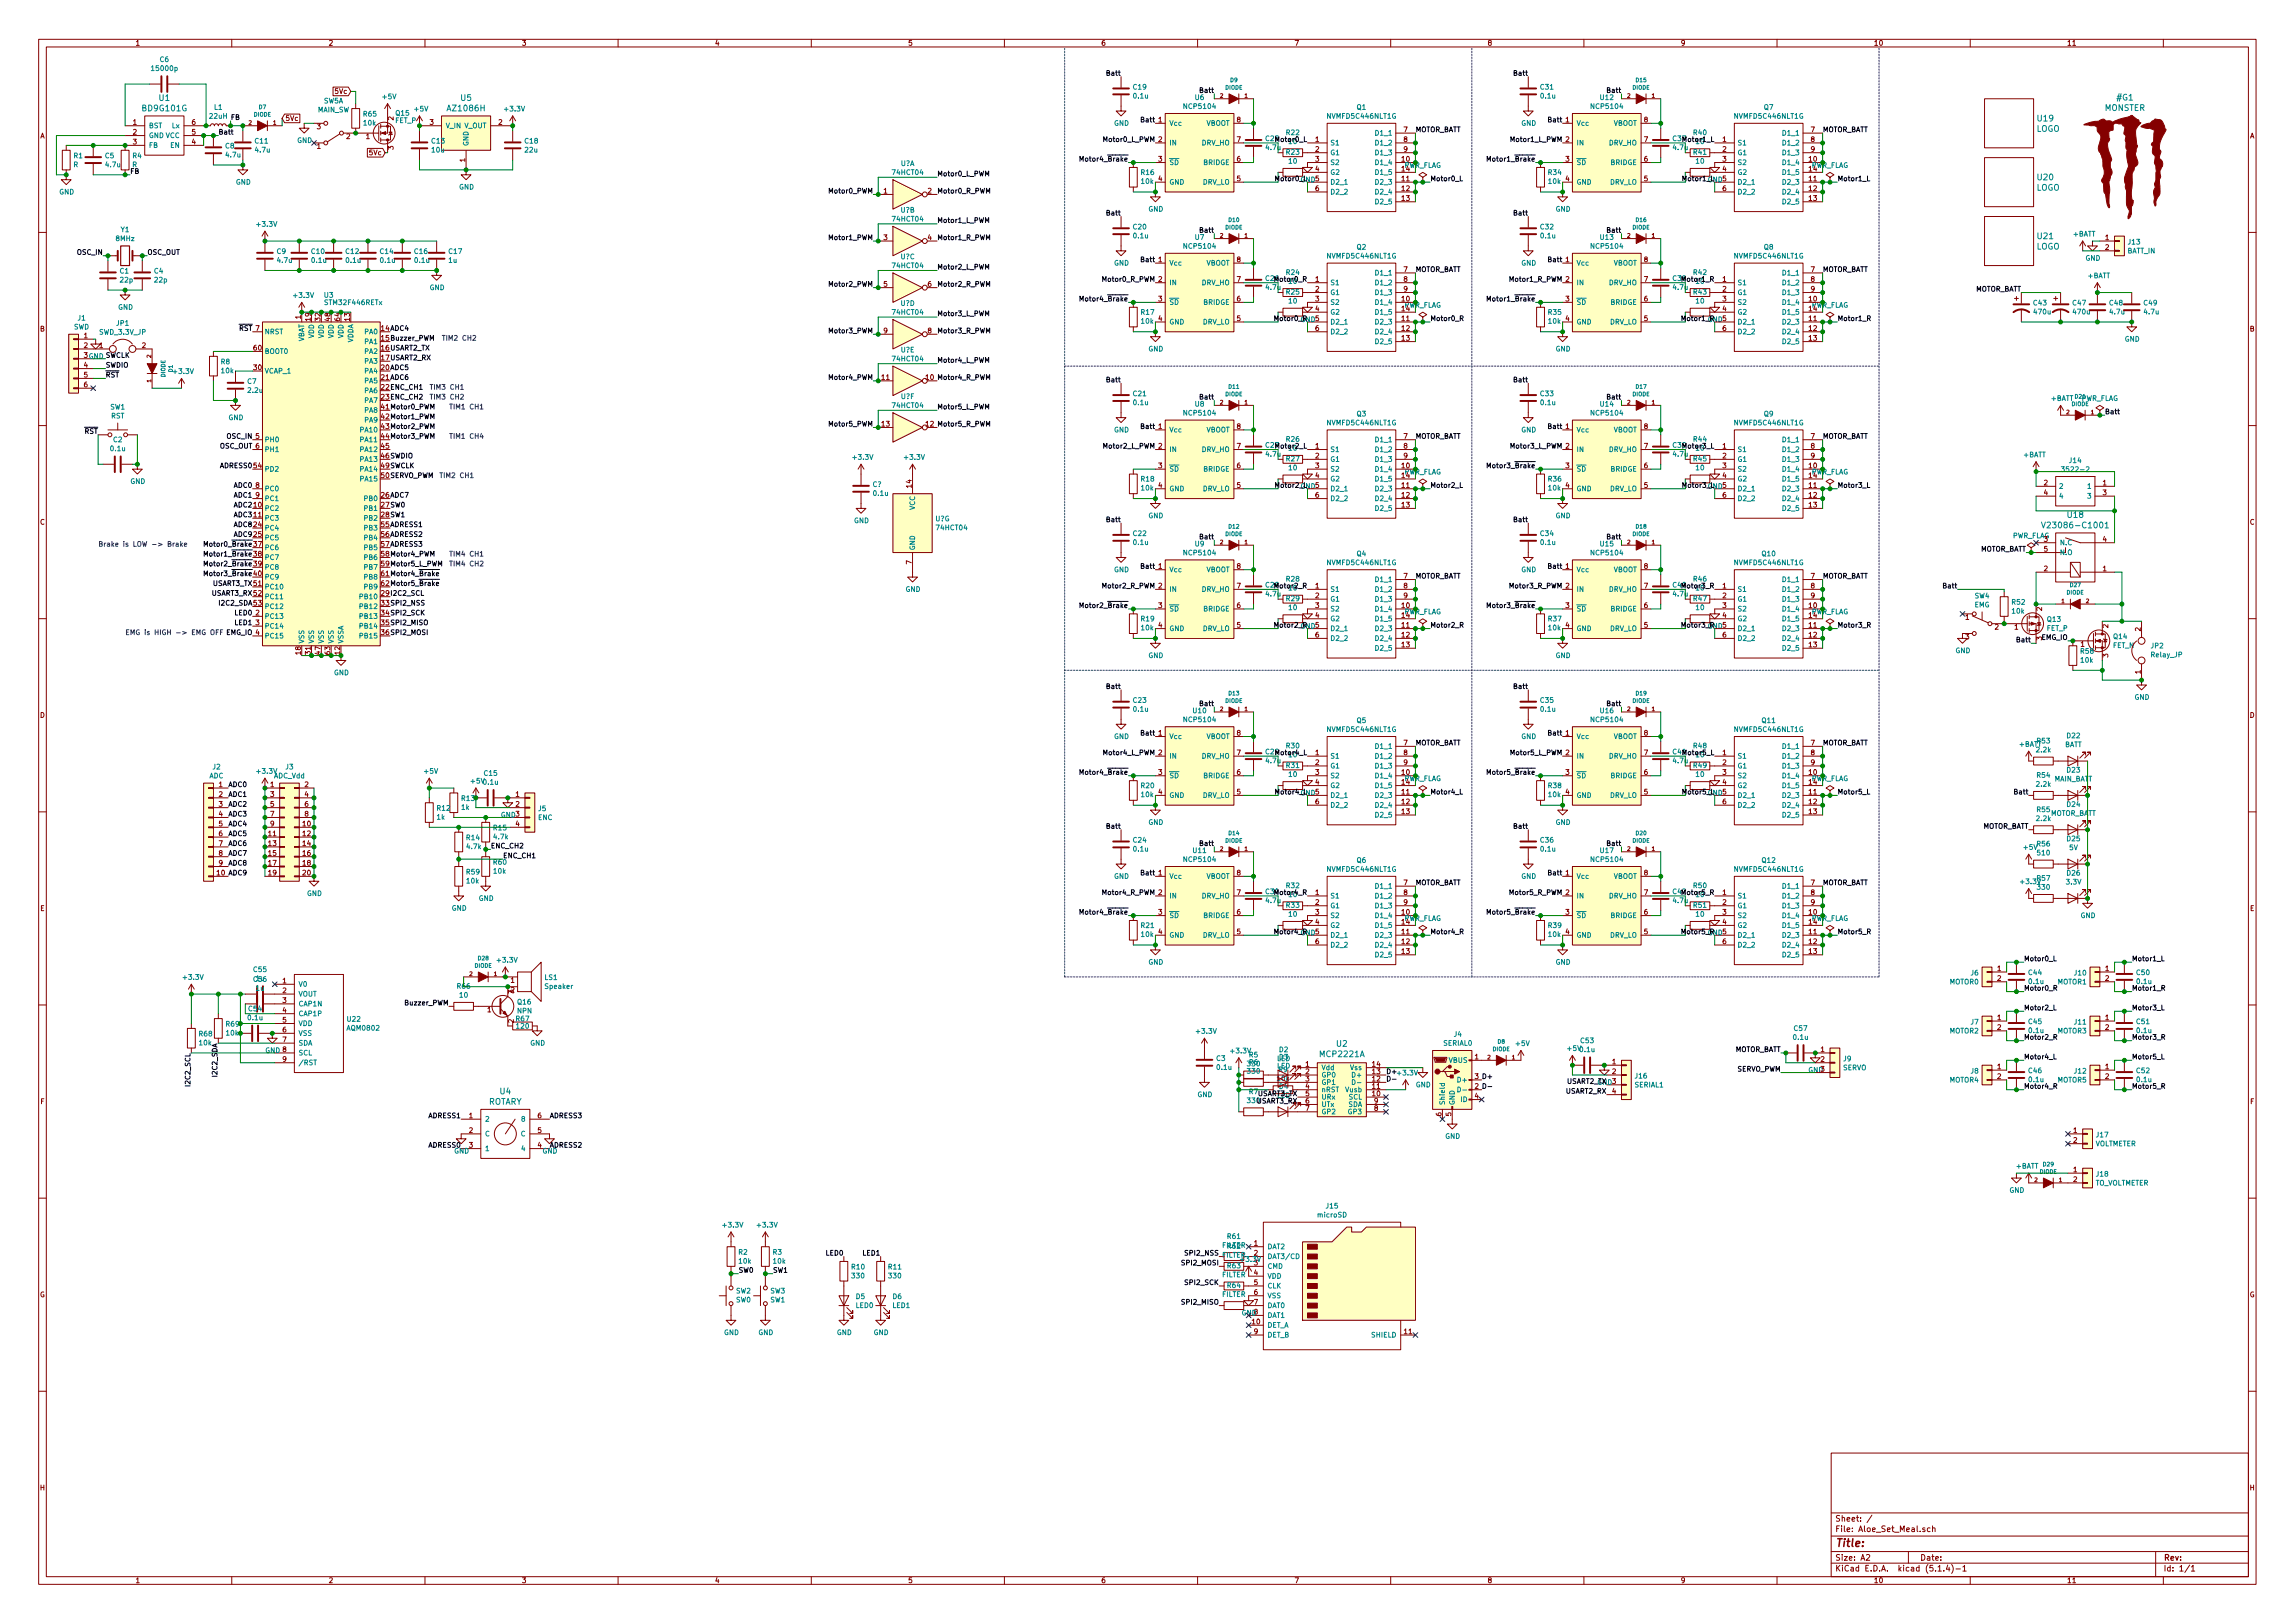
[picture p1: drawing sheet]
<svg xmlns="http://www.w3.org/2000/svg" width="594mm" height="420mm" viewBox="0 0 594 420" stroke-linecap="round" stroke-linejoin="round" font-family="sans-serif">
<defs><g id="words">
<text font-size="2.8" fill="#840000" x="475" y="400.4">Title:</text>
<g font-size="2.1" fill="#008484">
<text x="37" y="28.8">BD9G101G</text>
<text x="41.2" y="26.1">U1</text>
<text x="116.1" y="28.8">AZ1086H</text>
<text x="119.3" y="26.1">U5</text>
<text x="544.8" y="28.7">MONSTER</text>
<text x="548.1" y="26">#G1</text>
<text x="527" y="34.1">LOGO</text>
<text x="527.5" y="31.4">U19</text>
<text x="527.5" y="46.7">U20</text>
<text x="527" y="49.3">LOGO</text>
<text x="527" y="64.6">LOGO</text>
<text x="527.5" y="61.9">U21</text>
<text x="530.1" y="136.7">V23086-C1001</text>
<text x="535.3" y="134.1">U18</text>
<text x="341.9" y="273.7">MCP2221A</text>
<text x="346" y="271">U2</text>
<text x="126.3" y="286">ROTARY</text>
<text x="129.5" y="283.3">U4</text>
</g>
<g font-size="2.1" fill="#840000">
<text x="475" y="393.9">Sheet: /</text>
<text x="475" y="396.6">File: Aloe_Set_Meal.sch</text>
<text x="475" y="406.8">KiCad E.D.A. kicad (5.1.4)-1</text>
<text x="475" y="404">Size: A2</text>
<text x="497" y="404">Date:</text>
<text x="560" y="404">Rev:</text>
<text x="560" y="406.8">Id: 1/1</text>
</g>
<g font-size="1.8" fill="#840000">
<text x="35" y="11.8">1</text>
<text x="85" y="11.8">2</text>
<text x="135" y="11.8">3</text>
<text x="185" y="11.8">4</text>
<text x="235" y="11.8">5</text>
<text x="285" y="11.8">6</text>
<text x="335" y="11.8">7</text>
<text x="385" y="11.8">8</text>
<text x="435" y="11.8">9</text>
<text x="485" y="11.8">10</text>
<text x="535" y="11.8">11</text>
<text x="86.9" y="24.3">5Vc</text>
<text x="10.4" y="35.8">A</text>
<text x="34.4" y="32.3">1</text>
<text x="34.4" y="34.8">2</text>
<text x="49.7" y="34.8">5</text>
<text x="49.7" y="32.3">6</text>
<text x="73.8" y="31.3">5Vc</text>
<text x="82.1" y="33.4">3</text>
<text x="89.7" y="36">2</text>
<text x="94.8" y="36">1</text>
<text x="101.9" y="31.1" transform="rotate(-90 101.9 31.1)">2</text>
<text x="111.3" y="32.3">3</text>
<text x="129.1" y="32.3">2</text>
<text x="320.2" y="31.7">8</text>
<text x="363.4" y="34.2">7</text>
<text x="425.6" y="31.7">8</text>
<text x="468.8" y="34.2">7</text>
<text x="582.4" y="35.8">A</text>
<text x="34.4" y="37.4">3</text>
<text x="49.7" y="37.4">4</text>
<text x="82.1" y="38.5">1</text>
<text x="95.8" y="40.2">5Vc</text>
<text x="101.9" y="38.8" transform="rotate(-90 101.9 38.8)">3</text>
<text x="120.4" y="41.9" transform="rotate(-90 120.4 41.9)">1</text>
<text x="299.9" y="36.7">2</text>
<text x="299.9" y="41.8">3</text>
<text x="320.2" y="41.8">6</text>
<text x="320.2" y="36.7">7</text>
<text x="340.5" y="36.7">1</text>
<text x="340.5" y="39.3">2</text>
<text x="340.5" y="41.8">3</text>
<text x="362.9" y="41.8">10</text>
<text x="363.4" y="36.7">8</text>
<text x="363.4" y="39.3">9</text>
<text x="405.3" y="36.7">2</text>
<text x="405.3" y="41.8">3</text>
<text x="425.6" y="41.8">6</text>
<text x="425.6" y="36.7">7</text>
<text x="445.9" y="36.7">1</text>
<text x="445.9" y="39.3">2</text>
<text x="445.9" y="41.8">3</text>
<text x="468.3" y="41.8">10</text>
<text x="468.8" y="36.7">8</text>
<text x="468.8" y="39.3">9</text>
<text x="299.9" y="46.9">4</text>
<text x="320.2" y="46.9">5</text>
<text x="340.5" y="44.4">4</text>
<text x="362.9" y="46.9">11</text>
<text x="362.9" y="44.4">14</text>
<text x="405.3" y="46.9">4</text>
<text x="425.6" y="46.9">5</text>
<text x="445.9" y="44.4">4</text>
<text x="468.3" y="46.9">11</text>
<text x="468.3" y="44.4">14</text>
<text x="228.8" y="50.1">1</text>
<text x="240.2" y="50.1">2</text>
<text x="340.5" y="49.4">6</text>
<text x="362.9" y="49.4">12</text>
<text x="362.9" y="52">13</text>
<text x="445.9" y="49.4">6</text>
<text x="468.3" y="49.4">12</text>
<text x="468.3" y="52">13</text>
<text x="228.8" y="62.1">3</text>
<text x="240.2" y="62.1">4</text>
<text x="545" y="62.1">1</text>
<text x="545" y="64.7">2</text>
<text x="320.2" y="67.9">8</text>
<text x="363.4" y="70.4">7</text>
<text x="425.6" y="67.9">8</text>
<text x="468.8" y="70.4">7</text>
<text x="228.8" y="74.2">5</text>
<text x="240.2" y="74.2">6</text>
<text x="320.2" y="72.9">7</text>
<text x="340.5" y="72.9">1</text>
<text x="340.5" y="75.5">2</text>
<text x="363.4" y="72.9">8</text>
<text x="363.4" y="75.5">9</text>
<text x="425.6" y="72.9">7</text>
<text x="445.9" y="72.9">1</text>
<text x="445.9" y="75.5">2</text>
<text x="468.8" y="72.9">8</text>
<text x="468.8" y="75.5">9</text>
<text x="77.9" y="82.6" transform="rotate(-90 77.9 82.6)">1</text>
<text x="80.4" y="83" transform="rotate(-90 80.4 83)">19</text>
<text x="82.9" y="83" transform="rotate(-90 82.9 83)">32</text>
<text x="85.5" y="83" transform="rotate(-90 85.5 83)">48</text>
<text x="88" y="83" transform="rotate(-90 88 83)">64</text>
<text x="90.6" y="83" transform="rotate(-90 90.6 83)">13</text>
<text x="299.9" y="78">3</text>
<text x="299.9" y="83.1">4</text>
<text x="320.2" y="83.1">5</text>
<text x="320.2" y="78">6</text>
<text x="340.5" y="78">3</text>
<text x="340.5" y="80.6">4</text>
<text x="362.9" y="78">10</text>
<text x="362.9" y="83.1">11</text>
<text x="362.9" y="80.6">14</text>
<text x="405.3" y="78">3</text>
<text x="405.3" y="83.1">4</text>
<text x="425.6" y="83.1">5</text>
<text x="425.6" y="78">6</text>
<text x="445.9" y="78">3</text>
<text x="445.9" y="80.6">4</text>
<text x="468.3" y="78">10</text>
<text x="468.3" y="83.1">11</text>
<text x="468.3" y="80.6">14</text>
<text x="10.4" y="85.8">B</text>
<text x="21.7" y="87.5">1</text>
<text x="228.8" y="86.3">9</text>
<text x="240.2" y="86.3">8</text>
<text x="340.5" y="85.6">6</text>
<text x="362.9" y="85.6">12</text>
<text x="362.9" y="88.2">13</text>
<text x="445.9" y="85.6">6</text>
<text x="468.3" y="85.6">12</text>
<text x="468.3" y="88.2">13</text>
<text x="582.4" y="85.8">B</text>
<text x="21.7" y="90.1">2</text>
<text x="21.7" y="95.2">4</text>
<text x="25.7" y="90.1">1</text>
<text x="36.8" y="90.1">2</text>
<text x="65.7" y="90.7">60</text>
<text x="65.7" y="95.8">30</text>
<text x="21.7" y="97.7">5</text>
<text x="21.7" y="100.2">6</text>
<text x="228.3" y="98.3">11</text>
<text x="228.3" y="110.4">13</text>
<text x="320.2" y="111">8</text>
<text x="363.4" y="113.6">7</text>
<text x="425.6" y="111">8</text>
<text x="468.8" y="113.6">7</text>
<text x="98.7" y="116.1">45</text>
<text x="299.9" y="116.1">2</text>
<text x="320.2" y="116.1">7</text>
<text x="340.5" y="116.1">1</text>
<text x="340.5" y="118.7">2</text>
<text x="363.4" y="116.1">8</text>
<text x="363.4" y="118.7">9</text>
<text x="405.3" y="116.1">2</text>
<text x="425.6" y="116.1">7</text>
<text x="445.9" y="116.1">1</text>
<text x="445.9" y="118.7">2</text>
<text x="468.8" y="116.1">8</text>
<text x="468.8" y="118.7">9</text>
<text x="65.7" y="121.2">54</text>
<text x="299.9" y="121.2">3</text>
<text x="320.2" y="121.2">6</text>
<text x="340.5" y="121.2">3</text>
<text x="340.5" y="123.7">4</text>
<text x="362.9" y="121.2">10</text>
<text x="362.9" y="123.7">14</text>
<text x="405.3" y="121.2">3</text>
<text x="425.6" y="121.2">6</text>
<text x="445.9" y="121.2">3</text>
<text x="445.9" y="123.7">4</text>
<text x="468.3" y="121.2">10</text>
<text x="468.3" y="123.7">14</text>
<text x="529.1" y="125.6">2</text>
<text x="544.3" y="125.6">1</text>
<text x="65.7" y="131.4">10</text>
<text x="66.2" y="126.3">8</text>
<text x="66.2" y="128.8">9</text>
<text x="236" y="126.2" transform="rotate(-90 236 126.2)">14</text>
<text x="299.9" y="126.3">4</text>
<text x="320.2" y="126.3">5</text>
<text x="340.5" y="128.8">6</text>
<text x="362.9" y="126.3">11</text>
<text x="362.9" y="128.8">12</text>
<text x="362.9" y="131.4">13</text>
<text x="405.3" y="126.3">4</text>
<text x="425.6" y="126.3">5</text>
<text x="445.9" y="128.8">6</text>
<text x="468.3" y="126.3">11</text>
<text x="468.3" y="128.8">12</text>
<text x="468.3" y="131.4">13</text>
<text x="529.1" y="128.2">4</text>
<text x="544.3" y="128.2">3</text>
<text x="10.4" y="135.8">C</text>
<text x="65.7" y="133.9">11</text>
<text x="65.7" y="136.4">24</text>
<text x="582.4" y="135.8">C</text>
<text x="65.7" y="139">25</text>
<text x="529.1" y="140.3">3</text>
<text x="529.1" y="142.8">5</text>
<text x="544.3" y="140.3">4</text>
<text x="236" y="146.1" transform="rotate(-90 236 146.1)">7</text>
<text x="320.2" y="147.2">8</text>
<text x="363.4" y="149.8">7</text>
<text x="425.6" y="147.2">8</text>
<text x="468.8" y="149.8">7</text>
<text x="529.1" y="147.9">2</text>
<text x="544.3" y="147.9">1</text>
<text x="320.2" y="152.3">7</text>
<text x="340.5" y="152.3">1</text>
<text x="340.5" y="154.9">2</text>
<text x="363.4" y="152.3">8</text>
<text x="363.4" y="154.9">9</text>
<text x="425.6" y="152.3">7</text>
<text x="445.9" y="152.3">1</text>
<text x="445.9" y="154.9">2</text>
<text x="468.8" y="152.3">8</text>
<text x="468.8" y="154.9">9</text>
<text x="66.2" y="159.3">2</text>
<text x="66.2" y="161.8">3</text>
<text x="299.9" y="157.4">3</text>
<text x="320.2" y="157.4">6</text>
<text x="340.5" y="157.4">3</text>
<text x="340.5" y="159.9">4</text>
<text x="362.9" y="157.4">10</text>
<text x="362.9" y="159.9">14</text>
<text x="405.3" y="157.4">3</text>
<text x="425.6" y="157.4">6</text>
<text x="445.9" y="157.4">3</text>
<text x="445.9" y="159.9">4</text>
<text x="468.3" y="157.4">10</text>
<text x="468.3" y="159.9">14</text>
<text x="508.8" y="160.4">1</text>
<text x="528.6" y="158.1" transform="rotate(-90 528.6 158.1)">2</text>
<text x="299.9" y="162.5">4</text>
<text x="320.2" y="162.5">5</text>
<text x="340.5" y="165">6</text>
<text x="362.9" y="162.5">11</text>
<text x="362.9" y="165">12</text>
<text x="362.9" y="167.6">13</text>
<text x="405.3" y="162.5">4</text>
<text x="425.6" y="162.5">5</text>
<text x="445.9" y="165">6</text>
<text x="468.3" y="162.5">11</text>
<text x="468.3" y="165">12</text>
<text x="468.3" y="167.6">13</text>
<text x="508.8" y="165.5">3</text>
<text x="516.4" y="163">2</text>
<text x="521.5" y="163">1</text>
<text x="538.6" y="167.4">1</text>
<text x="545.7" y="162.6" transform="rotate(-90 545.7 162.6)">2</text>
<text x="554.1" y="163.4" transform="rotate(-90 554.1 163.4)">2</text>
<text x="77.9" y="169.4" transform="rotate(-90 77.9 169.4)">18</text>
<text x="80.4" y="169.4" transform="rotate(-90 80.4 169.4)">31</text>
<text x="82.9" y="169.4" transform="rotate(-90 82.9 169.4)">47</text>
<text x="85.5" y="169.4" transform="rotate(-90 85.5 169.4)">63</text>
<text x="88" y="169.4" transform="rotate(-90 88 169.4)">12</text>
<text x="545.7" y="170.2" transform="rotate(-90 545.7 170.2)">3</text>
<text x="554.1" y="174.4" transform="rotate(-90 554.1 174.4)">1</text>
<text x="10.4" y="185.8">D</text>
<text x="582.4" y="185.8">D</text>
<text x="320.2" y="190.4">8</text>
<text x="425.6" y="190.4">8</text>
<text x="299.9" y="195.5">2</text>
<text x="320.2" y="195.5">7</text>
<text x="340.5" y="195.5">1</text>
<text x="363.4" y="193">7</text>
<text x="363.4" y="195.5">8</text>
<text x="405.3" y="195.5">2</text>
<text x="425.6" y="195.5">7</text>
<text x="445.9" y="195.5">1</text>
<text x="468.8" y="193">7</text>
<text x="468.8" y="195.5">8</text>
<text x="56.7" y="203.8">1</text>
<text x="70" y="203.8">1</text>
<text x="78.9" y="203.8">2</text>
<text x="299.9" y="200.6">3</text>
<text x="320.2" y="200.6">6</text>
<text x="340.5" y="198">2</text>
<text x="340.5" y="200.6">3</text>
<text x="340.5" y="203.1">4</text>
<text x="362.9" y="200.6">10</text>
<text x="362.9" y="203.1">14</text>
<text x="363.4" y="198">9</text>
<text x="405.3" y="200.6">3</text>
<text x="425.6" y="200.6">6</text>
<text x="445.9" y="198">2</text>
<text x="445.9" y="200.6">3</text>
<text x="445.9" y="203.1">4</text>
<text x="468.3" y="200.6">10</text>
<text x="468.3" y="203.1">14</text>
<text x="468.8" y="198">9</text>
<text x="56.7" y="206.3">2</text>
<text x="56.7" y="208.8">3</text>
<text x="70" y="206.3">3</text>
<text x="70" y="208.8">5</text>
<text x="78.9" y="206.3">4</text>
<text x="78.9" y="208.8">6</text>
<text x="133.5" y="206.3">1</text>
<text x="133.5" y="208.8">2</text>
<text x="299.9" y="205.7">4</text>
<text x="320.2" y="205.7">5</text>
<text x="340.5" y="208.2">6</text>
<text x="362.9" y="205.7">11</text>
<text x="362.9" y="208.2">12</text>
<text x="405.3" y="205.7">4</text>
<text x="425.6" y="205.7">5</text>
<text x="445.9" y="208.2">6</text>
<text x="468.3" y="205.7">11</text>
<text x="468.3" y="208.2">12</text>
<text x="56.7" y="211.4">4</text>
<text x="56.7" y="213.9">5</text>
<text x="70" y="211.4">7</text>
<text x="70" y="213.9">9</text>
<text x="78.4" y="213.9">10</text>
<text x="78.9" y="211.4">8</text>
<text x="133.5" y="213.9">4</text>
<text x="362.9" y="210.7">13</text>
<text x="468.3" y="210.7">13</text>
<text x="56.7" y="216.5">6</text>
<text x="56.7" y="219">7</text>
<text x="56.7" y="221.5">8</text>
<text x="69.5" y="216.5">11</text>
<text x="69.5" y="219">13</text>
<text x="69.5" y="221.5">15</text>
<text x="78.4" y="216.5">12</text>
<text x="78.4" y="219">14</text>
<text x="78.4" y="221.5">16</text>
<text x="56.7" y="224.1">9</text>
<text x="69.5" y="224.1">17</text>
<text x="69.5" y="226.6">19</text>
<text x="78.4" y="224.1">18</text>
<text x="78.4" y="226.6">20</text>
<text x="320.2" y="226.6">8</text>
<text x="425.6" y="226.6">8</text>
<text x="320.2" y="231.7">7</text>
<text x="340.5" y="231.7">1</text>
<text x="363.4" y="229.2">7</text>
<text x="363.4" y="231.7">8</text>
<text x="425.6" y="231.7">7</text>
<text x="445.9" y="231.7">1</text>
<text x="468.8" y="229.2">7</text>
<text x="468.8" y="231.7">8</text>
<text x="10.4" y="235.8">E</text>
<text x="299.9" y="236.8">3</text>
<text x="320.2" y="236.8">6</text>
<text x="340.5" y="234.2">2</text>
<text x="340.5" y="236.8">3</text>
<text x="340.5" y="239.3">4</text>
<text x="362.9" y="236.8">10</text>
<text x="362.9" y="239.3">14</text>
<text x="363.4" y="234.2">9</text>
<text x="405.3" y="236.8">3</text>
<text x="425.6" y="236.8">6</text>
<text x="445.9" y="234.2">2</text>
<text x="445.9" y="236.8">3</text>
<text x="445.9" y="239.3">4</text>
<text x="468.3" y="236.8">10</text>
<text x="468.3" y="239.3">14</text>
<text x="468.8" y="234.2">9</text>
<text x="582.4" y="235.8">E</text>
<text x="299.9" y="241.9">4</text>
<text x="320.2" y="241.9">5</text>
<text x="340.5" y="244.4">6</text>
<text x="362.9" y="241.9">11</text>
<text x="362.9" y="244.4">12</text>
<text x="405.3" y="241.9">4</text>
<text x="425.6" y="241.9">5</text>
<text x="445.9" y="244.4">6</text>
<text x="468.3" y="241.9">11</text>
<text x="468.3" y="244.4">12</text>
<text x="362.9" y="246.9">13</text>
<text x="468.3" y="246.9">13</text>
<text x="517" y="251.4">1</text>
<text x="545" y="251.4">1</text>
<text x="73.2" y="254.6">1</text>
<text x="73.2" y="257.1">2</text>
<text x="132.2" y="254.4">1</text>
<text x="132.2" y="257">2</text>
<text x="133" y="257.2" transform="rotate(-90 133 257.2)">3</text>
<text x="517" y="253.9">2</text>
<text x="545" y="253.9">2</text>
<text x="73.2" y="259.6">3</text>
<text x="73.2" y="262.2">4</text>
<text x="126.2" y="262">1</text>
<text x="73.2" y="264.7">5</text>
<text x="73.2" y="267.3">6</text>
<text x="73.2" y="269.8">7</text>
<text x="133" y="264.8" transform="rotate(-90 133 264.8)">2</text>
<text x="517" y="264.1">1</text>
<text x="517" y="266.6">2</text>
<text x="545" y="264.1">1</text>
<text x="545" y="266.6">2</text>
<text x="73.2" y="274.9">9</text>
<text x="381.8" y="274.2">1</text>
<text x="417.3" y="275.5">1</text>
<text x="471.3" y="272.3">1</text>
<text x="471.3" y="274.9">2</text>
<text x="330.6" y="279.8">10k</text>
<text x="331.2" y="281.9">D4</text>
<text x="338" y="276.1">1</text>
<text x="338" y="278">2</text>
<text x="338" y="280">3</text>
<text x="338" y="281.9">4</text>
<text x="355.3" y="281.9">11</text>
<text x="355.3" y="280">12</text>
<text x="355.3" y="278">13</text>
<text x="355.3" y="276.1">14</text>
<text x="417.3" y="278">2</text>
<text x="468.1" y="277.7">GND3</text>
<text x="517" y="276.8">1</text>
<text x="517" y="279.3">2</text>
<text x="545" y="276.8">1</text>
<text x="545" y="279.3">2</text>
<text x="10.5" y="285.8">F</text>
<text x="338" y="283.8">5</text>
<text x="338" y="285.7">6</text>
<text x="338" y="287.6">7</text>
<text x="355.3" y="283.8">10</text>
<text x="355.8" y="287.6">8</text>
<text x="355.8" y="285.7">9</text>
<text x="381.8" y="284.4">4</text>
<text x="417.3" y="283.1">4</text>
<text x="582.5" y="285.8">F</text>
<text x="121.4" y="289.5">1</text>
<text x="121.4" y="293.3">2</text>
<text x="139.2" y="293.3">5</text>
<text x="139.2" y="289.5">6</text>
<text x="373.1" y="288.9" transform="rotate(-90 373.1 288.9)">6</text>
<text x="375.7" y="288.9" transform="rotate(-90 375.7 288.9)">5</text>
<text x="536.7" y="293.3">1</text>
<text x="121.4" y="297.1">3</text>
<text x="139.2" y="297.1">4</text>
<text x="536.7" y="295.8">2</text>
<text x="536.7" y="303.4">1</text>
<text x="536.7" y="306">2</text>
<text x="324.6" y="322.5">1</text>
<text x="324.6" y="325">2</text>
<text x="324.6" y="327.6">3</text>
<text x="10.3" y="335.8">G</text>
<text x="324.6" y="330.1">4</text>
<text x="324.6" y="332.7">5</text>
<text x="324.6" y="335.2">6</text>
<text x="582.3" y="335.8">G</text>
<text x="324.6" y="337.7">7</text>
<text x="324.2" y="342.8">10</text>
<text x="324.6" y="345.4">9</text>
<text x="363.5" y="345.4">11</text>
<text x="10.4" y="385.8">H</text>
<text x="582.4" y="385.8">H</text>
<text x="35" y="409.8">1</text>
<text x="85" y="409.8">2</text>
<text x="135" y="409.8">3</text>
<text x="185" y="409.8">4</text>
<text x="235" y="409.8">5</text>
<text x="285" y="409.8">6</text>
<text x="335" y="409.8">7</text>
<text x="385" y="409.8">8</text>
<text x="435" y="409.8">9</text>
<text x="485" y="409.8">10</text>
<text x="535" y="409.8">11</text>
</g>
<g font-size="1.8" fill="#008484">
<text x="41.4" y="16">C6</text>
<text x="39.5" y="18.4">15000p</text>
<text x="293.4" y="23.2">C19</text>
<text x="398.8" y="23.2">C31</text>
<text x="55.5" y="28.4">L1</text>
<text x="82.2" y="29.1">MAIN_SW</text>
<text x="83.8" y="26.8">SW5A</text>
<text x="99.1" y="25.7">+5V</text>
<text x="102.5" y="29.9">Q15</text>
<text x="107.4" y="28.8">+5V</text>
<text x="130.8" y="28.8">+3.3V</text>
<text x="293.5" y="25.5">0.1u</text>
<text x="306.7" y="28.2">NCP5104</text>
<text x="309.4" y="25.9">U6</text>
<text x="351.3" y="28.4">Q1</text>
<text x="398.9" y="25.5">0.1u</text>
<text x="412.1" y="28.2">NCP5104</text>
<text x="414.3" y="25.9">U12</text>
<text x="456.7" y="28.4">Q7</text>
<text x="38.5" y="33.2">BST</text>
<text x="38.5" y="35.7">GND VCC</text>
<text x="44.6" y="33.2">Lx</text>
<text x="94.1" y="30.2">R65</text>
<text x="94.2" y="32.5">10k</text>
<text x="102.3" y="31.8">FET_P</text>
<text x="115.3" y="33.2">V_IN V_OUT</text>
<text x="288.4" y="32.6">GND</text>
<text x="302.6" y="32.6">Vcc</text>
<text x="312.1" y="32.6">VBOOT</text>
<text x="333" y="35">R22</text>
<text x="343.8" y="30.7">NVMFD5C446NLT1G</text>
<text x="356.3" y="35.1">D1_1</text>
<text x="393.8" y="32.6">GND</text>
<text x="408.1" y="32.6">Vcc</text>
<text x="417.5" y="32.6">VBOOT</text>
<text x="438.4" y="35">R40</text>
<text x="449.2" y="30.7">NVMFD5C446NLT1G</text>
<text x="461.7" y="35.1">D1_1</text>
<text x="19.1" y="41">R1</text>
<text x="27.3" y="41">C5</text>
<text x="34.4" y="41">R4</text>
<text x="38.5" y="38.3">FB</text>
<text x="44.1" y="38.3">EN</text>
<text x="58.4" y="38.4">C8</text>
<text x="58.6" y="40.7">4.7u</text>
<text x="66.1" y="37.2">C11</text>
<text x="66.2" y="39.5">4.7u</text>
<text x="76.9" y="37">GND</text>
<text x="111.8" y="37.2">C13</text>
<text x="111.8" y="39.5">10u</text>
<text x="121.3" y="37.9" transform="rotate(-90 121.3 37.9)">GND</text>
<text x="135.9" y="37.2">C18</text>
<text x="136" y="39.5">22u</text>
<text x="302.6" y="37.6">IN</text>
<text x="311" y="37.6">DRV_HO</text>
<text x="327.8" y="38.8">4.7u</text>
<text x="333" y="40">R23</text>
<text x="344.3" y="37.6">S1</text>
<text x="344.3" y="40.2">G1</text>
<text x="356.3" y="37.6">D1_2</text>
<text x="356.3" y="40.2">D1_3</text>
<text x="408.1" y="37.6">IN</text>
<text x="416.4" y="37.6">DRV_HO</text>
<text x="433.2" y="38.8">4.7u</text>
<text x="438.4" y="40">R41</text>
<text x="449.7" y="37.6">S1</text>
<text x="449.7" y="40.2">G1</text>
<text x="461.7" y="37.6">D1_2</text>
<text x="461.7" y="40.2">D1_3</text>
<text x="19" y="43.3">R</text>
<text x="27.5" y="43.3">4.7u</text>
<text x="34.2" y="43.3">R</text>
<text x="61" y="47.8">GND</text>
<text x="231.2" y="45.3">74HCT04</text>
<text x="233.1" y="43">U?A</text>
<text x="295.4" y="45.3">R16</text>
<text x="295.5" y="47.6">10k</text>
<text x="302.6" y="42.7">SD</text>
<text x="302.6" y="47.8">GND</text>
<text x="311.2" y="47.8">DRV_LO</text>
<text x="311.5" y="42.7">BRIDGE</text>
<text x="333.7" y="42.4">10</text>
<text x="344.3" y="42.7">S2</text>
<text x="344.3" y="45.3">G2</text>
<text x="344.3" y="47.8">D2_1</text>
<text x="356.3" y="42.7">D1_4</text>
<text x="356.3" y="47.8">D2_3</text>
<text x="356.3" y="45.3">D1_5</text>
<text x="400.8" y="45.3">R34</text>
<text x="400.9" y="47.6">10k</text>
<text x="408.1" y="42.7">SD</text>
<text x="408.1" y="47.8">GND</text>
<text x="416.6" y="47.8">DRV_LO</text>
<text x="416.9" y="42.7">BRIDGE</text>
<text x="439.1" y="42.4">10</text>
<text x="449.7" y="42.7">S2</text>
<text x="449.7" y="45.3">G2</text>
<text x="449.7" y="47.8">D2_1</text>
<text x="461.7" y="42.7">D1_4</text>
<text x="461.7" y="47.8">D2_3</text>
<text x="461.7" y="45.3">D1_5</text>
<text x="15.3" y="50.3">GND</text>
<text x="118.8" y="49.1">GND</text>
<text x="344.3" y="50.3">D2_2</text>
<text x="356.3" y="50.3">D2_4</text>
<text x="356.3" y="52.9">D2_5</text>
<text x="449.7" y="50.3">D2_2</text>
<text x="461.7" y="50.3">D2_4</text>
<text x="461.7" y="52.9">D2_5</text>
<text x="66.6" y="58.7">+3.3V</text>
<text x="231.2" y="57.3">74HCT04</text>
<text x="233.1" y="55">U?B</text>
<text x="293.4" y="59.4">C20</text>
<text x="297.3" y="54.8">GND</text>
<text x="398.8" y="59.4">C32</text>
<text x="402.7" y="54.8">GND</text>
<text x="30.1" y="62.4">8MHz</text>
<text x="31.3" y="60.1">Y1</text>
<text x="71.7" y="65.7">C9</text>
<text x="80.7" y="65.7">C10</text>
<text x="89.6" y="65.7">C12</text>
<text x="98.5" y="65.7">C14</text>
<text x="107.3" y="65.7">C16</text>
<text x="116.2" y="65.7">C17</text>
<text x="293.5" y="61.7">0.1u</text>
<text x="306.7" y="64.4">NCP5104</text>
<text x="309.4" y="62.1">U7</text>
<text x="351.3" y="64.6">Q2</text>
<text x="398.9" y="61.7">0.1u</text>
<text x="412.1" y="64.4">NCP5104</text>
<text x="414.3" y="62.1">U13</text>
<text x="456.7" y="64.6">Q8</text>
<text x="536.6" y="61.2">+BATT</text>
<text x="550.6" y="65.6">BATT_IN</text>
<text x="551" y="63.3">J13</text>
<text x="31.1" y="70.8">C1</text>
<text x="40" y="70.8">C4</text>
<text x="71.9" y="68">4.7u</text>
<text x="80.8" y="68">0.1u</text>
<text x="89.7" y="68">0.1u</text>
<text x="98.6" y="68">0.1u</text>
<text x="107.5" y="68">0.1u</text>
<text x="116.2" y="68">1u</text>
<text x="231.2" y="69.4">74HCT04</text>
<text x="233.1" y="67.1">U?C</text>
<text x="288.4" y="68.7">GND</text>
<text x="302.6" y="68.7">Vcc</text>
<text x="312.1" y="68.7">VBOOT</text>
<text x="333" y="71.2">R24</text>
<text x="343.8" y="66.9">NVMFD5C446NLT1G</text>
<text x="356.3" y="71.3">D1_1</text>
<text x="393.8" y="68.7">GND</text>
<text x="408.1" y="68.7">Vcc</text>
<text x="417.5" y="68.7">VBOOT</text>
<text x="438.4" y="71.2">R42</text>
<text x="449.2" y="66.9">NVMFD5C446NLT1G</text>
<text x="461.7" y="71.3">D1_1</text>
<text x="539.8" y="67.5">GND</text>
<text x="31.2" y="73.1">22p</text>
<text x="40.1" y="73.1">22p</text>
<text x="76.1" y="77.1">+3.3V</text>
<text x="84" y="77.1">U3</text>
<text x="111.2" y="75.1">GND</text>
<text x="302.6" y="73.8">IN</text>
<text x="311" y="73.8">DRV_HO</text>
<text x="327.8" y="75">4.7u</text>
<text x="333" y="76.2">R25</text>
<text x="344.3" y="73.8">S1</text>
<text x="344.3" y="76.4">G1</text>
<text x="356.3" y="73.8">D1_2</text>
<text x="356.3" y="76.4">D1_3</text>
<text x="408.1" y="73.8">IN</text>
<text x="416.4" y="73.8">DRV_HO</text>
<text x="433.2" y="75">4.7u</text>
<text x="438.4" y="76.2">R43</text>
<text x="449.7" y="73.8">S1</text>
<text x="449.7" y="76.4">G1</text>
<text x="461.7" y="73.8">D1_2</text>
<text x="461.7" y="76.4">D1_3</text>
<text x="540.4" y="72">+BATT</text>
<text x="20.2" y="83">J1</text>
<text x="30.6" y="80.2">GND</text>
<text x="84.3" y="79">STM32F446RETx</text>
<text x="231.2" y="81.5">74HCT04</text>
<text x="233.1" y="79.2">U?D</text>
<text x="295.4" y="81.5">R17</text>
<text x="295.5" y="83.8">10k</text>
<text x="302.6" y="78.9">SD</text>
<text x="302.6" y="84">GND</text>
<text x="311.2" y="84">DRV_LO</text>
<text x="311.5" y="78.9">BRIDGE</text>
<text x="333.7" y="78.6">10</text>
<text x="344.3" y="78.9">S2</text>
<text x="344.3" y="81.4">G2</text>
<text x="344.3" y="84">D2_1</text>
<text x="356.3" y="78.9">D1_4</text>
<text x="356.3" y="84">D2_3</text>
<text x="356.3" y="81.4">D1_5</text>
<text x="400.8" y="81.5">R35</text>
<text x="400.9" y="83.8">10k</text>
<text x="408.1" y="78.9">SD</text>
<text x="408.1" y="84">GND</text>
<text x="416.6" y="84">DRV_LO</text>
<text x="416.9" y="78.9">BRIDGE</text>
<text x="439.1" y="78.6">10</text>
<text x="449.7" y="78.9">S2</text>
<text x="449.7" y="81.4">G2</text>
<text x="449.7" y="84">D2_1</text>
<text x="461.7" y="78.9">D1_4</text>
<text x="461.7" y="84">D2_3</text>
<text x="461.7" y="81.4">D1_5</text>
<text x="526.4" y="79.1">C43</text>
<text x="526.6" y="81.4">470u</text>
<text x="536.6" y="79.1">C47</text>
<text x="536.8" y="81.4">470u</text>
<text x="546.1" y="79.1">C48</text>
<text x="546.3" y="81.4">4.7u</text>
<text x="555" y="79.1">C49</text>
<text x="555.1" y="81.4">4.7u</text>
<text x="19" y="85.3">SWD</text>
<text x="25.8" y="86.6">SWD_3.3V_JP</text>
<text x="30.2" y="84.3">JP1</text>
<text x="68.5" y="86.5">NRST</text>
<text x="78.7" y="88.7" transform="rotate(-90 78.7 88.7)">VBAT</text>
<text x="81.3" y="87.6" transform="rotate(-90 81.3 87.6)">VDD</text>
<text x="83.8" y="87.6" transform="rotate(-90 83.8 87.6)">VDD</text>
<text x="86.4" y="87.6" transform="rotate(-90 86.4 87.6)">VDD</text>
<text x="88.9" y="87.6" transform="rotate(-90 88.9 87.6)">VDD</text>
<text x="91.4" y="88.9" transform="rotate(-90 91.4 88.9)">VDDA</text>
<text x="94.5" y="86.5">PA0</text>
<text x="94.5" y="89.1">PA1</text>
<text x="344.3" y="86.5">D2_2</text>
<text x="356.3" y="86.5">D2_4</text>
<text x="356.3" y="89.1">D2_5</text>
<text x="449.7" y="86.5">D2_2</text>
<text x="461.7" y="86.5">D2_4</text>
<text x="461.7" y="89.1">D2_5</text>
<text x="550" y="88.4">GND</text>
<text x="57.2" y="94.3">R8</text>
<text x="68.5" y="91.6">BOOT0</text>
<text x="94.5" y="91.6">PA2</text>
<text x="94.5" y="94.1">PA3</text>
<text x="231.2" y="93.5">74HCT04</text>
<text x="233.2" y="91.2">U?E</text>
<text x="297.3" y="91">GND</text>
<text x="402.7" y="91">GND</text>
<text x="45" y="96.8">+3.3V</text>
<text x="57.4" y="96.6">10k</text>
<text x="64.1" y="99.4">C7</text>
<text x="64.3" y="101.7">2.2u</text>
<text x="68.5" y="96.7">VCAP_1</text>
<text x="94.5" y="96.7">PA4</text>
<text x="94.5" y="99.2">PA5</text>
<text x="94.5" y="101.8">PA6</text>
<text x="28.6" y="106">SW1</text>
<text x="94.5" y="104.3">PA7</text>
<text x="94.5" y="106.8">PA8</text>
<text x="231.2" y="105.6">74HCT04</text>
<text x="233.2" y="103.3">U?F</text>
<text x="293.4" y="102.6">C21</text>
<text x="293.5" y="104.9">0.1u</text>
<text x="306.7" y="107.6">NCP5104</text>
<text x="309.4" y="105.2">U8</text>
<text x="351.3" y="107.8">Q3</text>
<text x="398.8" y="102.6">C33</text>
<text x="398.9" y="104.9">0.1u</text>
<text x="412.1" y="107.6">NCP5104</text>
<text x="414.3" y="105.2">U14</text>
<text x="456.7" y="107.8">Q9</text>
<text x="530.9" y="103.8">+BATT</text>
<text x="538.6" y="103.8">PWR_FLAG</text>
<text x="28.7" y="108.3">RST</text>
<text x="59.1" y="108.8">GND</text>
<text x="93.5" y="111.9">PA10</text>
<text x="94.5" y="109.4">PA9</text>
<text x="288.4" y="111.9">GND</text>
<text x="302.6" y="111.9">Vcc</text>
<text x="312.1" y="111.9">VBOOT</text>
<text x="343.8" y="110.1">NVMFD5C446NLT1G</text>
<text x="393.8" y="111.9">GND</text>
<text x="408.1" y="111.9">Vcc</text>
<text x="417.5" y="111.9">VBOOT</text>
<text x="449.2" y="110.1">NVMFD5C446NLT1G</text>
<text x="28.7" y="116.8">0.1u</text>
<text x="29.4" y="114.5">C2</text>
<text x="68.5" y="114.5">PH0</text>
<text x="68.5" y="117">PH1</text>
<text x="93.5" y="114.5">PA11</text>
<text x="93.5" y="117">PA12</text>
<text x="93.5" y="119.5">PA13</text>
<text x="220.9" y="119">+3.3V</text>
<text x="234.3" y="119">+3.3V</text>
<text x="302.6" y="117">IN</text>
<text x="311" y="117">DRV_HO</text>
<text x="327.8" y="118.2">4.7u</text>
<text x="333" y="119.4">R27</text>
<text x="333" y="114.3">R26</text>
<text x="344.3" y="117">S1</text>
<text x="344.3" y="119.5">G1</text>
<text x="356.3" y="114.5">D1_1</text>
<text x="356.3" y="117">D1_2</text>
<text x="356.3" y="119.5">D1_3</text>
<text x="408.1" y="117">IN</text>
<text x="416.4" y="117">DRV_HO</text>
<text x="433.2" y="118.2">4.7u</text>
<text x="438.4" y="114.3">R44</text>
<text x="438.4" y="119.4">R45</text>
<text x="449.7" y="117">S1</text>
<text x="449.7" y="119.5">G1</text>
<text x="461.7" y="114.5">D1_1</text>
<text x="461.7" y="117">D1_2</text>
<text x="461.7" y="119.5">D1_3</text>
<text x="523.8" y="118.4">+BATT</text>
<text x="535.7" y="119.9">J14</text>
<text x="33.7" y="125.3">GND</text>
<text x="68.5" y="122.1">PD2</text>
<text x="93.5" y="122.1">PA14</text>
<text x="93.5" y="124.6">PA15</text>
<text x="295.4" y="124.7">R18</text>
<text x="302.6" y="122.1">SD</text>
<text x="311.5" y="122.1">BRIDGE</text>
<text x="333.7" y="121.7">10</text>
<text x="344.3" y="122.1">S2</text>
<text x="344.3" y="124.6">G2</text>
<text x="356.3" y="122.1">D1_4</text>
<text x="356.3" y="124.6">D1_5</text>
<text x="400.8" y="124.7">R36</text>
<text x="408.1" y="122.1">SD</text>
<text x="416.9" y="122.1">BRIDGE</text>
<text x="439.1" y="121.7">10</text>
<text x="449.7" y="122.1">S2</text>
<text x="449.7" y="124.6">G2</text>
<text x="461.7" y="122.1">D1_4</text>
<text x="461.7" y="124.6">D1_5</text>
<text x="534.5" y="122.2">3522-2</text>
<text x="68.5" y="127.2">PC0</text>
<text x="68.5" y="129.7">PC1</text>
<text x="94.5" y="129.7">PB0</text>
<text x="225.9" y="126.1">C?</text>
<text x="226.2" y="128.4">0.1u</text>
<text x="295.5" y="127">10k</text>
<text x="302.6" y="127.2">GND</text>
<text x="311.2" y="127.2">DRV_LO</text>
<text x="344.3" y="127.2">D2_1</text>
<text x="344.3" y="129.7">D2_2</text>
<text x="356.3" y="127.2">D2_3</text>
<text x="356.3" y="129.7">D2_4</text>
<text x="400.9" y="127">10k</text>
<text x="408.1" y="127.2">GND</text>
<text x="416.6" y="127.2">DRV_LO</text>
<text x="449.7" y="127.2">D2_1</text>
<text x="449.7" y="129.7">D2_2</text>
<text x="461.7" y="127.2">D2_3</text>
<text x="461.7" y="129.7">D2_4</text>
<text x="532.9" y="126.5">2</text>
<text x="532.9" y="129.1">4</text>
<text x="540.5" y="126.5">1</text>
<text x="540.5" y="129.1">3</text>
<text x="68.5" y="132.2">PC2</text>
<text x="68.5" y="134.8">PC3</text>
<text x="68.5" y="137.3">PC4</text>
<text x="94.5" y="132.2">PB1</text>
<text x="94.5" y="134.8">PB2</text>
<text x="94.5" y="137.3">PB3</text>
<text x="221.1" y="135.4">GND</text>
<text x="236.9" y="132" transform="rotate(-90 236.9 132)">VCC</text>
<text x="242.1" y="134.9">U?G</text>
<text x="242.5" y="137.3">74HCT04</text>
<text x="297.3" y="134.2">GND</text>
<text x="356.3" y="132.2">D2_5</text>
<text x="402.7" y="134.2">GND</text>
<text x="461.7" y="132.2">D2_5</text>
<text x="68.5" y="139.9">PC5</text>
<text x="68.5" y="142.4">PC6</text>
<text x="94.5" y="139.9">PB4</text>
<text x="94.5" y="142.4">PB5</text>
<text x="236.9" y="142.5" transform="rotate(-90 236.9 142.5)">GND</text>
<text x="293.4" y="138.8">C22</text>
<text x="293.5" y="141.1">0.1u</text>
<text x="306.7" y="143.8">NCP5104</text>
<text x="309.4" y="141.4">U9</text>
<text x="351.3" y="144">Q4</text>
<text x="398.8" y="138.8">C34</text>
<text x="398.9" y="141.1">0.1u</text>
<text x="412.1" y="143.8">NCP5104</text>
<text x="414.3" y="141.4">U15</text>
<text x="456.2" y="144">Q10</text>
<text x="520.8" y="139.3">PWR_FLAG</text>
<text x="533.1" y="141.1">N.C</text>
<text x="533.1" y="143.7">N.O</text>
<text x="68.5" y="144.9">PC7</text>
<text x="68.5" y="147.5">PC8</text>
<text x="94.5" y="144.9">PB6</text>
<text x="94.5" y="147.5">PB7</text>
<text x="288.4" y="148.1">GND</text>
<text x="302.6" y="148.1">Vcc</text>
<text x="312.1" y="148.1">VBOOT</text>
<text x="343.8" y="146.3">NVMFD5C446NLT1G</text>
<text x="393.8" y="148.1">GND</text>
<text x="408.1" y="148.1">Vcc</text>
<text x="417.5" y="148.1">VBOOT</text>
<text x="449.2" y="146.3">NVMFD5C446NLT1G</text>
<text x="68.5" y="152.6">PC10</text>
<text x="68.5" y="155.1">PC11</text>
<text x="68.5" y="150">PC9</text>
<text x="93.5" y="155.1">PB10</text>
<text x="94.5" y="150">PB8</text>
<text x="94.5" y="152.6">PB9</text>
<text x="234.4" y="153.2">GND</text>
<text x="302.6" y="153.2">IN</text>
<text x="311" y="153.2">DRV_HO</text>
<text x="327.8" y="154.4">4.7u</text>
<text x="333" y="150.5">R28</text>
<text x="333" y="155.6">R29</text>
<text x="344.3" y="153.2">S1</text>
<text x="344.3" y="155.7">G1</text>
<text x="356.3" y="150.7">D1_1</text>
<text x="356.3" y="153.2">D1_2</text>
<text x="356.3" y="155.7">D1_3</text>
<text x="408.1" y="153.2">IN</text>
<text x="416.4" y="153.2">DRV_HO</text>
<text x="433.2" y="154.4">4.7u</text>
<text x="438.4" y="150.5">R46</text>
<text x="438.4" y="155.6">R47</text>
<text x="449.7" y="153.2">S1</text>
<text x="449.7" y="155.7">G1</text>
<text x="461.7" y="150.7">D1_1</text>
<text x="461.7" y="153.2">D1_2</text>
<text x="461.7" y="155.7">D1_3</text>
<text x="511.2" y="154.9">SW4</text>
<text x="68.5" y="157.6">PC12</text>
<text x="68.5" y="160.2">PC13</text>
<text x="93.5" y="157.6">PB12</text>
<text x="93.5" y="160.2">PB13</text>
<text x="295.4" y="160.8">R19</text>
<text x="302.6" y="158.3">SD</text>
<text x="311.5" y="158.3">BRIDGE</text>
<text x="333.7" y="157.9">10</text>
<text x="344.3" y="158.3">S2</text>
<text x="344.3" y="160.8">G2</text>
<text x="356.3" y="158.3">D1_4</text>
<text x="356.3" y="160.8">D1_5</text>
<text x="400.8" y="160.8">R37</text>
<text x="408.1" y="158.3">SD</text>
<text x="416.9" y="158.3">BRIDGE</text>
<text x="439.1" y="157.9">10</text>
<text x="449.7" y="158.3">S2</text>
<text x="449.7" y="160.8">G2</text>
<text x="461.7" y="158.3">D1_4</text>
<text x="461.7" y="160.8">D1_5</text>
<text x="511.1" y="157.2">EMG</text>
<text x="520.9" y="156.5">R52</text>
<text x="520.9" y="158.8">10k</text>
<text x="530" y="161">Q13</text>
<text x="68.5" y="162.7">PC14</text>
<text x="68.5" y="165.3">PC15</text>
<text x="78.7" y="166.7" transform="rotate(-90 78.7 166.7)">VSS</text>
<text x="81.3" y="166.7" transform="rotate(-90 81.3 166.7)">VSS</text>
<text x="83.8" y="166.7" transform="rotate(-90 83.8 166.7)">VSS</text>
<text x="86.4" y="166.7" transform="rotate(-90 86.4 166.7)">VSS</text>
<text x="88.9" y="166.7" transform="rotate(-90 88.9 166.7)">VSSA</text>
<text x="93.5" y="162.7">PB14</text>
<text x="93.5" y="165.3">PB15</text>
<text x="295.5" y="163.2">10k</text>
<text x="302.6" y="163.4">GND</text>
<text x="311.2" y="163.4">DRV_LO</text>
<text x="344.3" y="163.4">D2_1</text>
<text x="344.3" y="165.9">D2_2</text>
<text x="356.3" y="163.4">D2_3</text>
<text x="356.3" y="165.9">D2_4</text>
<text x="400.9" y="163.2">10k</text>
<text x="408.1" y="163.4">GND</text>
<text x="416.6" y="163.4">DRV_LO</text>
<text x="449.7" y="163.4">D2_1</text>
<text x="449.7" y="165.9">D2_2</text>
<text x="461.7" y="163.4">D2_3</text>
<text x="461.7" y="165.9">D2_4</text>
<text x="529.8" y="163.3">FET_P</text>
<text x="546.9" y="167.7">FET_N</text>
<text x="547.2" y="165.4">Q14</text>
<text x="556.8" y="167.8">JP2</text>
<text x="297.3" y="170.3">GND</text>
<text x="356.3" y="168.4">D2_5</text>
<text x="402.7" y="170.3">GND</text>
<text x="461.7" y="168.4">D2_5</text>
<text x="506.2" y="169.1">GND</text>
<text x="538.6" y="169.2">R58</text>
<text x="538.7" y="171.5">10k</text>
<text x="556.9" y="170.1">Relay_JP</text>
<text x="86.4" y="174.8">GND</text>
<text x="293.4" y="181.9">C23</text>
<text x="293.5" y="184.2">0.1u</text>
<text x="308.9" y="184.6">U10</text>
<text x="398.8" y="181.9">C35</text>
<text x="398.9" y="184.2">0.1u</text>
<text x="414.3" y="184.6">U16</text>
<text x="552.5" y="181.1">GND</text>
<text x="288.4" y="191.3">GND</text>
<text x="302.6" y="191.3">Vcc</text>
<text x="306.7" y="186.9">NCP5104</text>
<text x="312.1" y="191.3">VBOOT</text>
<text x="343.8" y="189.5">NVMFD5C446NLT1G</text>
<text x="351.3" y="187.2">Q5</text>
<text x="393.8" y="191.3">GND</text>
<text x="408.1" y="191.3">Vcc</text>
<text x="412.1" y="186.9">NCP5104</text>
<text x="417.5" y="191.3">VBOOT</text>
<text x="449.2" y="189.5">NVMFD5C446NLT1G</text>
<text x="456.2" y="187.2">Q11</text>
<text x="535.1" y="191.1">D22</text>
<text x="302.6" y="196.4">IN</text>
<text x="311" y="196.4">DRV_HO</text>
<text x="327.8" y="197.6">4.7u</text>
<text x="333" y="193.7">R30</text>
<text x="344.3" y="196.4">S1</text>
<text x="356.3" y="193.8">D1_1</text>
<text x="356.3" y="196.4">D1_2</text>
<text x="408.1" y="196.4">IN</text>
<text x="416.4" y="196.4">DRV_HO</text>
<text x="433.2" y="197.6">4.7u</text>
<text x="438.4" y="193.7">R48</text>
<text x="449.7" y="196.4">S1</text>
<text x="461.7" y="193.8">D1_1</text>
<text x="461.7" y="196.4">D1_2</text>
<text x="522.7" y="193.3">+BATT</text>
<text x="527.2" y="194.8">2.2k</text>
<text x="527.3" y="192.4">R53</text>
<text x="534.4" y="193.4">BATT</text>
<text x="54.1" y="201.5">ADC</text>
<text x="55.1" y="199.2">J2</text>
<text x="66.6" y="200.3">+3.3V</text>
<text x="70.9" y="201.5">ADC_Vdd</text>
<text x="74" y="199.2">J3</text>
<text x="109.9" y="200.3">+5V</text>
<text x="122" y="202.8">+5V0.1u</text>
<text x="125.4" y="200.8">C15</text>
<text x="302.6" y="201.5">SD</text>
<text x="311.5" y="201.5">BRIDGE</text>
<text x="333" y="198.8">R31</text>
<text x="333.7" y="201.1">10</text>
<text x="344.3" y="198.9">G1</text>
<text x="344.3" y="201.5">S2</text>
<text x="356.3" y="201.5">D1_4</text>
<text x="356.3" y="198.9">D1_3</text>
<text x="408.1" y="201.5">SD</text>
<text x="416.9" y="201.5">BRIDGE</text>
<text x="438.4" y="198.8">R49</text>
<text x="439.1" y="201.1">10</text>
<text x="449.7" y="198.9">G1</text>
<text x="449.7" y="201.5">S2</text>
<text x="461.7" y="201.5">D1_4</text>
<text x="461.7" y="198.9">D1_3</text>
<text x="527.2" y="203.6">2.2k</text>
<text x="527.3" y="201.3">R54</text>
<text x="531.6" y="202.3">MAIN_BATT</text>
<text x="535.1" y="200">D23</text>
<text x="113.2" y="209.9">R12</text>
<text x="119.5" y="209.6">1k</text>
<text x="119.5" y="207.3">R13</text>
<text x="139.4" y="210">J5</text>
<text x="295.4" y="204">R20</text>
<text x="295.5" y="206.3">10k</text>
<text x="302.6" y="206.5">GND</text>
<text x="311.2" y="206.5">DRV_LO</text>
<text x="344.3" y="204">G2</text>
<text x="344.3" y="206.5">D2_1</text>
<text x="344.3" y="209.1">D2_2</text>
<text x="356.3" y="206.5">D2_3</text>
<text x="356.3" y="209.1">D2_4</text>
<text x="356.3" y="204">D1_5</text>
<text x="400.8" y="204">R38</text>
<text x="400.9" y="206.3">10k</text>
<text x="408.1" y="206.5">GND</text>
<text x="416.6" y="206.5">DRV_LO</text>
<text x="449.7" y="204">G2</text>
<text x="449.7" y="206.5">D2_1</text>
<text x="449.7" y="209.1">D2_2</text>
<text x="461.7" y="206.5">D2_3</text>
<text x="461.7" y="209.1">D2_4</text>
<text x="461.7" y="204">D1_5</text>
<text x="535.1" y="208.9">D24</text>
<text x="113.1" y="212.2">1k</text>
<text x="127.8" y="215">R15</text>
<text x="129.6" y="211.6">GND3</text>
<text x="139.3" y="212.3">ENC</text>
<text x="297.3" y="213.5">GND</text>
<text x="356.3" y="211.6">D2_5</text>
<text x="402.7" y="213.5">GND</text>
<text x="461.7" y="211.6">D2_5</text>
<text x="527.2" y="212.5">2.2k</text>
<text x="527.3" y="210.2">R55</text>
<text x="530.6" y="211.2">MOTOR_BATT</text>
<text x="120.8" y="217.5">R14</text>
<text x="120.9" y="219.8">4.7k</text>
<text x="127.9" y="217.3">4.7k</text>
<text x="293.4" y="218.1">C24</text>
<text x="293.5" y="220.4">0.1u</text>
<text x="308.9" y="220.8">U11</text>
<text x="398.8" y="218.1">C36</text>
<text x="398.9" y="220.4">0.1u</text>
<text x="414.3" y="220.8">U17</text>
<text x="523.9" y="220">+5V</text>
<text x="527.3" y="219.1">R56</text>
<text x="527.5" y="221.4">510</text>
<text x="535.1" y="217.8">D25</text>
<text x="535.7" y="220.1">5V</text>
<text x="120.8" y="226.4">R59</text>
<text x="127.8" y="223.8">R60</text>
<text x="127.8" y="226.2">10k</text>
<text x="288.4" y="227.5">GND</text>
<text x="302.6" y="227.5">Vcc</text>
<text x="306.7" y="223.1">NCP5104</text>
<text x="312.1" y="227.5">VBOOT</text>
<text x="343.8" y="225.7">NVMFD5C446NLT1G</text>
<text x="351.3" y="223.4">Q6</text>
<text x="393.8" y="227.5">GND</text>
<text x="408.1" y="227.5">Vcc</text>
<text x="412.1" y="223.1">NCP5104</text>
<text x="417.5" y="227.5">VBOOT</text>
<text x="449.2" y="225.7">NVMFD5C446NLT1G</text>
<text x="456.2" y="223.4">Q12</text>
<text x="535.1" y="226.7">D26</text>
<text x="79.5" y="231.9">GND</text>
<text x="120.9" y="228.7">10k</text>
<text x="123.9" y="233.2">GND</text>
<text x="302.6" y="232.6">IN</text>
<text x="311" y="232.6">DRV_HO</text>
<text x="327.8" y="233.8">4.7u</text>
<text x="333" y="229.9">R32</text>
<text x="344.3" y="232.6">S1</text>
<text x="356.3" y="230">D1_1</text>
<text x="356.3" y="232.6">D1_2</text>
<text x="408.1" y="232.6">IN</text>
<text x="416.4" y="232.6">DRV_HO</text>
<text x="433.2" y="233.8">4.7u</text>
<text x="438.4" y="229.9">R50</text>
<text x="449.7" y="232.6">S1</text>
<text x="461.7" y="230">D1_1</text>
<text x="461.7" y="232.6">D1_2</text>
<text x="523.2" y="228.9">+3.3V</text>
<text x="527.3" y="228">R57</text>
<text x="527.5" y="230.3">330</text>
<text x="534.9" y="229">3.3V</text>
<text x="116.9" y="235.8">GND</text>
<text x="302.6" y="237.7">SD</text>
<text x="311.5" y="237.7">BRIDGE</text>
<text x="333" y="235">R33</text>
<text x="333.7" y="237.3">10</text>
<text x="344.3" y="235.1">G1</text>
<text x="344.3" y="237.7">S2</text>
<text x="356.3" y="237.7">D1_4</text>
<text x="356.3" y="235.1">D1_3</text>
<text x="408.1" y="237.7">SD</text>
<text x="416.9" y="237.7">BRIDGE</text>
<text x="438.4" y="235">R51</text>
<text x="439.1" y="237.3">10</text>
<text x="449.7" y="235.1">G1</text>
<text x="449.7" y="237.7">S2</text>
<text x="461.7" y="237.7">D1_4</text>
<text x="461.7" y="235.1">D1_3</text>
<text x="538.6" y="237.7">GND</text>
<text x="295.4" y="240.2">R21</text>
<text x="295.5" y="242.5">10k</text>
<text x="302.6" y="242.7">GND</text>
<text x="311.2" y="242.7">DRV_LO</text>
<text x="344.3" y="240.2">G2</text>
<text x="344.3" y="242.7">D2_1</text>
<text x="344.3" y="245.3">D2_2</text>
<text x="356.3" y="242.7">D2_3</text>
<text x="356.3" y="245.3">D2_4</text>
<text x="356.3" y="240.2">D1_5</text>
<text x="400.8" y="240.2">R39</text>
<text x="400.9" y="242.5">10k</text>
<text x="408.1" y="242.7">GND</text>
<text x="416.6" y="242.7">DRV_LO</text>
<text x="449.7" y="240.2">G2</text>
<text x="449.7" y="242.7">D2_1</text>
<text x="449.7" y="245.3">D2_2</text>
<text x="461.7" y="242.7">D2_3</text>
<text x="461.7" y="245.3">D2_4</text>
<text x="461.7" y="240.2">D1_5</text>
<text x="65.7" y="251.6">C55</text>
<text x="128.9" y="249.2">+3.3V</text>
<text x="297.3" y="249.7">GND</text>
<text x="356.3" y="247.8">D2_5</text>
<text x="402.7" y="249.7">GND</text>
<text x="461.7" y="247.8">D2_5</text>
<text x="47.6" y="253.6">+3.3V</text>
<text x="65.7" y="254.2">C56</text>
<text x="66.3" y="253.9">1u</text>
<text x="66.3" y="256.5">1u</text>
<text x="77.2" y="255.4">V0</text>
<text x="77.2" y="258">VOUT</text>
<text x="118.4" y="255.9">R66</text>
<text x="141" y="253.7">LS1</text>
<text x="141.2" y="256">Speaker</text>
<text x="504.7" y="254.8">MOTOR0</text>
<text x="510.2" y="252.5">J6</text>
<text x="525.2" y="252.4">C44</text>
<text x="525.3" y="254.7">0.1u</text>
<text x="532.6" y="254.8">MOTOR1</text>
<text x="537" y="252.5">J10</text>
<text x="553.1" y="252.4">C50</text>
<text x="553.2" y="254.7">0.1u</text>
<text x="64.4" y="261.8">C54</text>
<text x="77.2" y="260.5">CAP1N</text>
<text x="77.2" y="263.1">CAP1P</text>
<text x="119" y="258.3">10</text>
<text x="133.9" y="262.3">NPN</text>
<text x="134" y="260">Q16</text>
<text x="51.6" y="268.3">R68</text>
<text x="58.6" y="265.8">R69</text>
<text x="58.6" y="268.1">10k</text>
<text x="64.3" y="264.1">0.1u</text>
<text x="77.2" y="265.6">VDD</text>
<text x="77.2" y="268.1">VSS</text>
<text x="89.9" y="264.5">U22</text>
<text x="90" y="266.8">AQM0802</text>
<text x="133.6" y="264.4">R67</text>
<text x="133.8" y="266.3">120</text>
<text x="309.8" y="267.6">+3.3V</text>
<text x="376.4" y="268.4">J4</text>
<text x="464.3" y="269.2">0.1u</text>
<text x="464.5" y="266.9">C57</text>
<text x="504.7" y="267.5">MOTOR2</text>
<text x="510.2" y="265.2">J7</text>
<text x="525.2" y="265.1">C45</text>
<text x="525.3" y="267.4">0.1u</text>
<text x="532.6" y="267.5">MOTOR3</text>
<text x="537" y="265.2">J11</text>
<text x="553.1" y="265.1">C51</text>
<text x="553.2" y="267.4">0.1u</text>
<text x="51.6" y="270.6">10k</text>
<text x="68.7" y="272.6">GND 8</text>
<text x="77.2" y="270.7">SDA</text>
<text x="77.2" y="273.2">SCL</text>
<text x="77.2" y="275.8">/RST</text>
<text x="137.2" y="270.7">GND</text>
<text x="314.9" y="274.6">C3</text>
<text x="318.7" y="272.7">+3.3V</text>
<text x="323.4" y="273.7">R5</text>
<text x="323.4" y="275.6">R6</text>
<text x="331.2" y="274.3">D3</text>
<text x="331.2" y="272.4">D2</text>
<text x="373.6" y="270.7">SERIAL0</text>
<text x="375.1" y="275.1">VBUS</text>
<text x="392.5" y="270.8">+5V</text>
<text x="405.8" y="272.1">+5V0.1u</text>
<text x="409.2" y="270">C53</text>
<text x="477.2" y="274.7">J9</text>
<text x="315.1" y="277">0.1u</text>
<text x="323" y="277.9">330</text>
<text x="330.5" y="276.6">LED</text>
<text x="331" y="277.5">R9</text>
<text x="342" y="277">Vdd</text>
<text x="342" y="278.9">GP0</text>
<text x="342" y="280.8">GP1</text>
<text x="349.5" y="277">Vss</text>
<text x="350.4" y="278.9">D+</text>
<text x="366.5" y="281.5">GND</text>
<text x="377.7" y="280.2">D+</text>
<text x="423.2" y="281.5">SERIAL1</text>
<text x="423.3" y="279.2">J16</text>
<text x="477" y="277.1">SERVO</text>
<text x="504.7" y="280.2">MOTOR4</text>
<text x="510.2" y="277.9">J8</text>
<text x="525.2" y="277.8">C46</text>
<text x="525.3" y="280.1">0.1u</text>
<text x="532.6" y="280.2">MOTOR5</text>
<text x="537" y="277.9">J12</text>
<text x="553.1" y="277.8">C52</text>
<text x="553.2" y="280.1">0.1u</text>
<text x="310" y="284">GND</text>
<text x="323.4" y="283.3">R7</text>
<text x="342" y="282.7">nRST</text>
<text x="342" y="284.6">URx</text>
<text x="342" y="286.6">UTx</text>
<text x="348.4" y="282.7">Vusb</text>
<text x="348.9" y="286.6">SDA</text>
<text x="349.1" y="284.6">SCL</text>
<text x="374" y="286.2" transform="rotate(-90 374 286.2)">Shield</text>
<text x="376.6" y="286.2" transform="rotate(-90 376.6 286.2)">GND</text>
<text x="378.2" y="285.3">ID</text>
<text x="125.5" y="290.4">2</text>
<text x="135.2" y="290.4">8</text>
<text x="342" y="288.5">GP2</text>
<text x="349.1" y="288.5">GP3</text>
<text x="117.6" y="298.6">GND</text>
<text x="125.5" y="294.2">C</text>
<text x="125.5" y="298">1</text>
<text x="134.9" y="294.2">C</text>
<text x="135.2" y="298">4</text>
<text x="140.4" y="298.6">GND</text>
<text x="374.1" y="294.8">GND</text>
<text x="542.3" y="296.7">VOLTMETER</text>
<text x="542.7" y="294.4">J17</text>
<text x="521.9" y="302.5">+BATT</text>
<text x="542.7" y="304.6">J18</text>
<text x="520.1" y="308.8">GND</text>
<text x="542.2" y="306.9">TO_VOLTMETER</text>
<text x="187.3" y="317.8">+3.3V</text>
<text x="196.2" y="317.8">+3.3V</text>
<text x="341.2" y="315.2">microSD</text>
<text x="343.3" y="312.8">J15</text>
<text x="316.3" y="323">FILTER</text>
<text x="317.8" y="320.7">R61</text>
<text x="317.8" y="323.3">R62</text>
<text x="328" y="323.4">DAT2</text>
<text x="191.2" y="324.8">R2</text>
<text x="191.3" y="327.1">10k</text>
<text x="200.1" y="324.8">R3</text>
<text x="200.2" y="327.1">10k</text>
<text x="220.5" y="328.6">R10</text>
<text x="230" y="328.6">R11</text>
<text x="316.3" y="325.6">FILTER</text>
<text x="317.8" y="328.3">R63</text>
<text x="321.3" y="326.7">+3.3V</text>
<text x="328" y="325.9">DAT3/CD</text>
<text x="328" y="328.5">CMD</text>
<text x="190.6" y="334.8">SW2</text>
<text x="199.4" y="334.8">SW3</text>
<text x="220.6" y="330.9">330</text>
<text x="230.1" y="330.9">330</text>
<text x="316.3" y="330.6">FILTER</text>
<text x="316.3" y="335.7">FILTER</text>
<text x="317.8" y="333.4">R64</text>
<text x="328" y="331">VDD</text>
<text x="328" y="333.5">CLK</text>
<text x="190.6" y="337.2">SW0</text>
<text x="199.4" y="337.2">SW1</text>
<text x="221.5" y="338.6">LED0</text>
<text x="221.6" y="336.3">D5</text>
<text x="231.1" y="338.6">LED1</text>
<text x="231.1" y="336.3">D6</text>
<text x="328" y="336.1">VSS</text>
<text x="328" y="338.6">DAT0</text>
<text x="328" y="341.2">DAT1</text>
<text x="187.4" y="345.6">GND</text>
<text x="196.3" y="345.6">GND</text>
<text x="216.6" y="345.6">GND</text>
<text x="226.1" y="345.6">GND</text>
<text x="328" y="343.7">DET_A</text>
<text x="328" y="346.2">DET_B</text>
<text x="355.1" y="346.2">SHIELD</text>
</g>
<g font-size="1.8">
<text x="286.8" y="19.6">Batt</text>
<text x="392.2" y="19.6">Batt</text>
<text x="310.9" y="24">Batt</text>
<text x="416.3" y="24">Batt</text>
<text x="54.3" y="30.7">22uH FB</text>
<text x="56.5" y="34.8">Batt</text>
<text x="295.7" y="31.7">Batt 1</text>
<text x="366.4" y="34.2">MOTOR_BATT</text>
<text x="401.1" y="31.7">Batt 1</text>
<text x="471.8" y="34.2">MOTOR_BATT</text>
<text x="280.3" y="41.8">Motor4_Brake</text>
<text x="285.8" y="36.7">Motor0_L_PWM</text>
<text x="327.7" y="36.5">C25Motor0_L</text>
<text x="333.7" y="37.3">10</text>
<text x="385.7" y="41.8">Motor1_Brake</text>
<text x="391.2" y="36.7">Motor1_L_PWM</text>
<text x="433.1" y="36.5">C37Motor1_L</text>
<text x="439.1" y="37.3">10</text>
<text x="33.7" y="45">FB</text>
<text x="242.6" y="45.6">Motor0_L_PWM</text>
<text x="330.5" y="46.9">Motor0_L</text>
<text x="336.6" y="47.2">GND5</text>
<text x="370.2" y="46.9">Motor0_L</text>
<text x="435.9" y="46.9">Motor1_L</text>
<text x="442" y="47.2">GND5</text>
<text x="475.6" y="46.9">Motor1_L</text>
<text x="214.9" y="50.1">Motor0_PWM</text>
<text x="242.6" y="50.1">Motor0_R_PWM</text>
<text x="242.6" y="57.7">Motor1_L_PWM</text>
<text x="286.8" y="55.8">Batt</text>
<text x="392.2" y="55.8">Batt</text>
<text x="20.1" y="66">OSC_IN</text>
<text x="38.1" y="66">OSC_OUT</text>
<text x="214.9" y="62.1">Motor1_PWM</text>
<text x="242.6" y="62.1">Motor1_R_PWM</text>
<text x="310.9" y="60.2">Batt</text>
<text x="416.3" y="60.2">Batt</text>
<text x="242.6" y="69.8">Motor2_L_PWM</text>
<text x="295.7" y="67.9">Batt 1</text>
<text x="366.4" y="70.4">MOTOR_BATT</text>
<text x="401.1" y="67.9">Batt 1</text>
<text x="471.8" y="70.4">MOTOR_BATT</text>
<text x="214.9" y="74.2">Motor2_PWM</text>
<text x="242.6" y="74.2">Motor2_R_PWM</text>
<text x="285.6" y="72.9">Motor0_R_PWM 2</text>
<text x="327.7" y="72.7">C26Motor0_R</text>
<text x="333.7" y="73.5">10</text>
<text x="391" y="72.9">Motor1_R_PWM 2</text>
<text x="433.1" y="72.7">C38Motor1_R</text>
<text x="439.1" y="73.5">10</text>
<text x="510.9" y="75.5">MOTOR_BATT</text>
<text x="242.6" y="81.8">Motor3_L_PWM</text>
<text x="280.3" y="78">Motor4_Brake</text>
<text x="330.3" y="83.1">Motor0_R</text>
<text x="336.6" y="83.4">GND5</text>
<text x="370.2" y="83.1">Motor0_R</text>
<text x="385.7" y="78">Motor1_Brake</text>
<text x="435.7" y="83.1">Motor1_R</text>
<text x="442" y="83.4">GND5</text>
<text x="475.6" y="83.1">Motor1_R</text>
<text x="61.9" y="85.6">RST 7</text>
<text x="98.7" y="85.6">14ADC4</text>
<text x="98.7" y="88.2">15Buzzer_PWM</text>
<text x="214.9" y="86.3">Motor3_PWM</text>
<text x="242.6" y="86.3">Motor3_R_PWM</text>
<text x="21.7" y="92.6">3GND SWCLK</text>
<text x="27.3" y="95.2">SWDIO</text>
<text x="98.7" y="90.7">16USART2_TX</text>
<text x="98.7" y="93.3">17USART2_RX</text>
<text x="98.7" y="95.8">20ADC5</text>
<text x="242.6" y="93.9">Motor4_L_PWM</text>
<text x="27.3" y="97.7">RST</text>
<text x="98.7" y="98.3">21ADC6</text>
<text x="98.7" y="100.9">22ENC_CH1</text>
<text x="214.9" y="98.3">Motor4_PWM</text>
<text x="239.7" y="98.3">10 Motor4_R_PWM</text>
<text x="286.8" y="99">Batt</text>
<text x="392.2" y="99">Batt</text>
<text x="98.7" y="103.4">23ENC_CH2</text>
<text x="98.7" y="106">41Motor0_PWM</text>
<text x="242.6" y="106">Motor5_L_PWM</text>
<text x="310.9" y="103.4">Batt</text>
<text x="416.3" y="103.4">Batt</text>
<text x="544.8" y="107.2">Batt</text>
<text x="21.9" y="112.3">RST</text>
<text x="58.8" y="113.6">OSC_IN 5</text>
<text x="98.7" y="111">43Motor2_PWM</text>
<text x="98.7" y="113.6">44Motor3_PWM</text>
<text x="98.7" y="108.5">42Motor1_PWM</text>
<text x="214.9" y="110.4">Motor5_PWM</text>
<text x="239.7" y="110.4">12 Motor5_R_PWM</text>
<text x="295.7" y="111">Batt 1</text>
<text x="366.4" y="113.6">MOTOR_BATT</text>
<text x="401.1" y="111">Batt 1</text>
<text x="471.8" y="113.6">MOTOR_BATT</text>
<text x="56.8" y="116.1">OSC_OUT 6</text>
<text x="98.7" y="118.7">46SWDIO</text>
<text x="285.8" y="116.1">Motor2_L_PWM</text>
<text x="327.7" y="115.9">C27Motor2_L</text>
<text x="333.7" y="116.7">10</text>
<text x="391.2" y="116.1">Motor3_L_PWM</text>
<text x="433.1" y="115.9">C39Motor3_L</text>
<text x="439.1" y="116.7">10</text>
<text x="57" y="121.2">ADRESS0</text>
<text x="98.7" y="121.2">49SWCLK</text>
<text x="385.7" y="121.2">Motor3_Brake</text>
<text x="60.6" y="131.4">ADC2</text>
<text x="60.6" y="128.8">ADC1</text>
<text x="60.6" y="126.3">ADC0</text>
<text x="98.7" y="128.8">26ADC7</text>
<text x="98.7" y="131.4">27SW0</text>
<text x="330.5" y="126.3">Motor2_L</text>
<text x="336.6" y="126.5">GND5</text>
<text x="370.2" y="126.3">Motor2_L</text>
<text x="435.9" y="126.3">Motor3_L</text>
<text x="442" y="126.5">GND5</text>
<text x="475.6" y="126.3">Motor3_L</text>
<text x="60.6" y="136.4">ADC8</text>
<text x="60.6" y="133.9">ADC3</text>
<text x="98.7" y="133.9">28SW1</text>
<text x="98.7" y="136.4">55ADRESS1</text>
<text x="286.8" y="135.2">Batt</text>
<text x="392.2" y="135.2">Batt</text>
<text x="53.6" y="141.5">Motor0_Brake 37</text>
<text x="60.6" y="139">ADC9</text>
<text x="98.7" y="139">56ADRESS2</text>
<text x="98.7" y="141.5">57ADRESS3</text>
<text x="310.9" y="139.6">Batt</text>
<text x="416.3" y="139.6">Batt</text>
<text x="512.2" y="142.8">MOTOR_BATT</text>
<text x="53.6" y="146.6">Motor2_Brake 39</text>
<text x="53.6" y="149.1">Motor3_Brake 40</text>
<text x="53.6" y="144.1">Motor1_Brake 38</text>
<text x="98.7" y="144.1">58Motor4_PWM</text>
<text x="98.7" y="146.6">59Motor5_L_PWM</text>
<text x="98.7" y="149.1">61Motor4_Brake</text>
<text x="295.7" y="147.2">Batt 1</text>
<text x="366.4" y="149.8">MOTOR_BATT</text>
<text x="401.1" y="147.2">Batt 1</text>
<text x="471.8" y="149.8">MOTOR_BATT</text>
<text x="54.9" y="154.2">USART3_RX 52</text>
<text x="55.1" y="151.7">USART3_TX 51</text>
<text x="98.7" y="154.2">29I2C2_SCL</text>
<text x="98.7" y="151.7">62Motor5_Brake</text>
<text x="285.6" y="152.3">Motor2_R_PWM 2</text>
<text x="327.7" y="152.1">C28Motor2_R</text>
<text x="333.7" y="152.8">10</text>
<text x="391" y="152.3">Motor3_R_PWM 2</text>
<text x="433.1" y="152.1">C40Motor3_R</text>
<text x="439.1" y="152.8">10</text>
<text x="503.3" y="152.3">Batt</text>
<text x="56.9" y="156.8">I2C2_SDA 53</text>
<text x="60.9" y="159.3">LED0</text>
<text x="60.9" y="161.8">LED1</text>
<text x="98.7" y="156.8">33SPI2_NSS</text>
<text x="98.7" y="159.3">34SPI2_SCK</text>
<text x="98.7" y="161.8">35SPI2_MISO</text>
<text x="280.3" y="157.4">Motor2_Brake</text>
<text x="385.7" y="157.4">Motor3_Brake</text>
<text x="58.5" y="164.4">EMG_IO 4</text>
<text x="98.7" y="164.4">36SPI2_MOSI</text>
<text x="330.3" y="162.5">Motor2_R</text>
<text x="336.6" y="162.7">GND5</text>
<text x="370.2" y="162.5">Motor2_R</text>
<text x="435.7" y="162.5">Motor3_R</text>
<text x="442" y="162.7">GND5</text>
<text x="475.6" y="162.5">Motor3_R</text>
<text x="522.4" y="166.3">Batt</text>
<text x="528.4" y="165.7">EMG_IO</text>
<text x="528.6" y="165.8" transform="rotate(-90 528.6 165.8)">3</text>
<text x="286.8" y="178.4">Batt</text>
<text x="392.2" y="178.4">Batt</text>
<text x="310.9" y="182.8">Batt</text>
<text x="416.3" y="182.8">Batt</text>
<text x="295.7" y="190.4">Batt 1</text>
<text x="401.1" y="190.4">Batt 1</text>
<text x="285.8" y="195.5">Motor4_L_PWM</text>
<text x="327.7" y="195.3">C29Motor4_L</text>
<text x="333.7" y="196">10</text>
<text x="366.4" y="193">MOTOR_BATT</text>
<text x="391.2" y="195.5">Motor5_L_PWM</text>
<text x="433.1" y="195.3">C41Motor5_L</text>
<text x="439.1" y="196">10</text>
<text x="471.8" y="193">MOTOR_BATT</text>
<text x="59.1" y="203.8">ADC0</text>
<text x="280.3" y="200.6">Motor4_Brake</text>
<text x="385.7" y="200.6">Motor5_Brake</text>
<text x="59.1" y="208.8">ADC2</text>
<text x="59.1" y="206.3">ADC1</text>
<text x="330.5" y="205.7">Motor4_L</text>
<text x="336.6" y="205.9">GND5</text>
<text x="370.2" y="205.7">Motor4_L</text>
<text x="435.9" y="205.7">Motor5_L</text>
<text x="442" y="205.9">GND5</text>
<text x="475.6" y="205.7">Motor5_L</text>
<text x="521.7" y="205.7">Batt</text>
<text x="59.1" y="213.9">ADC4</text>
<text x="59.1" y="211.4">ADC3</text>
<text x="286.8" y="214.5">Batt</text>
<text x="392.2" y="214.5">Batt</text>
<text x="512.9" y="214.5">MOTOR_BATT</text>
<text x="59.1" y="221.5">ADC7</text>
<text x="59.1" y="219">ADC6</text>
<text x="59.1" y="216.5">ADC5</text>
<text x="127" y="219.6">ENC_CH2</text>
<text x="310.9" y="219">Batt</text>
<text x="416.3" y="219">Batt</text>
<text x="56.2" y="226.6">10 ADC9</text>
<text x="59.1" y="224.1">ADC8</text>
<text x="130.2" y="222.2">ENC_CH1</text>
<text x="295.7" y="226.6">Batt 1</text>
<text x="401.1" y="226.6">Batt 1</text>
<text x="285.6" y="231.7">Motor4_R_PWM 2</text>
<text x="327.7" y="231.5">C30Motor4_R</text>
<text x="333.7" y="232.2">10</text>
<text x="366.4" y="229.2">MOTOR_BATT</text>
<text x="391" y="231.7">Motor5_R_PWM 2</text>
<text x="433.1" y="231.5">C42Motor5_R</text>
<text x="439.1" y="232.2">10</text>
<text x="471.8" y="229.2">MOTOR_BATT</text>
<text x="280.3" y="236.8">Motor4_Brake</text>
<text x="385.7" y="236.8">Motor5_Brake</text>
<text x="330.3" y="241.9">Motor4_R</text>
<text x="336.6" y="242.1">GND5</text>
<text x="370.2" y="241.9">Motor4_R</text>
<text x="435.7" y="241.9">Motor5_R</text>
<text x="442" y="242.1">GND5</text>
<text x="475.6" y="241.9">Motor5_R</text>
<text x="523.9" y="248.8">Motor0_L</text>
<text x="551.8" y="248.8">Motor1_L</text>
<text x="523.9" y="256.5">Motor0_R</text>
<text x="551.8" y="256.5">Motor1_R</text>
<text x="105.1" y="260.3">Buzzer_PWM</text>
<text x="523.9" y="261.5">Motor2_L</text>
<text x="551.8" y="261.5">Motor3_L</text>
<text x="523.9" y="269.2">Motor2_R</text>
<text x="551.8" y="269.2">Motor3_R</text>
<text x="448.7" y="272.3">MOTOR_BATT</text>
<text x="523.9" y="274.2">Motor4_L</text>
<text x="551.8" y="274.2">Motor5_L</text>
<text x="49.3" y="280.8" transform="rotate(-90 49.3 280.8)">I2C2_SCL</text>
<text x="56.3" y="278.5" transform="rotate(-90 56.3 278.5)">I2C2_SDA</text>
<text x="358.8" y="278">D+ +3.3V</text>
<text x="381.8" y="281.9">2 D-</text>
<text x="381.8" y="279.3">3 D+</text>
<text x="405.6" y="280.6">USART2_TX</text>
<text x="413.5" y="280.8">GND3</text>
<text x="449.5" y="277.4">SERVO_PWM</text>
<text x="523.9" y="281.9">Motor4_R</text>
<text x="551.8" y="281.9">Motor5_R</text>
<text x="323" y="285.6">330USART3_RX</text>
<text x="325.6" y="283.8">USART3_TX</text>
<text x="330.5" y="284.2">LED</text>
<text x="405.4" y="283.1">USART2_RX</text>
<text x="111" y="289.5">ADRESS1</text>
<text x="142.2" y="289.5">ADRESS3</text>
<text x="111" y="297.1">ADRESS0</text>
<text x="142.2" y="297.1">ADRESS2</text>
<text x="191.1" y="329.5">SW0</text>
<text x="200" y="329.5">SW1</text>
<text x="213.9" y="325">LED0</text>
<text x="223.4" y="325">LED1</text>
<text x="306.2" y="327.6">SPI2_MOSI</text>
<text x="307.1" y="325">SPI2_NSS</text>
<text x="307" y="332.7">SPI2_SCK</text>
<text x="306.2" y="337.7">SPI2_MISO</text>
</g>
<g font-size="1.8" fill="#008400">
<text x="363.3" y="43.5">PWR_FLAG</text>
<text x="468.8" y="43.5">PWR_FLAG</text>
<text x="363.3" y="79.6">PWR_FLAG</text>
<text x="468.8" y="79.6">PWR_FLAG</text>
<text x="363.3" y="122.8">PWR_FLAG</text>
<text x="468.8" y="122.8">PWR_FLAG</text>
<text x="363.3" y="159">PWR_FLAG</text>
<text x="468.8" y="159">PWR_FLAG</text>
<text x="363.3" y="202.2">PWR_FLAG</text>
<text x="468.8" y="202.2">PWR_FLAG</text>
<text x="363.3" y="238.4">PWR_FLAG</text>
<text x="468.8" y="238.4">PWR_FLAG</text>
</g>
<g font-size="1.8" fill="#0000c2">
<text x="114.3" y="88.2">TIM2 CH2</text>
<text x="111.1" y="100.9">TIM3 CH1</text>
<text x="111.1" y="103.4">TIM3 CH2</text>
<text x="116.2" y="106">TIM1 CH1</text>
<text x="116.2" y="113.6">TIM1 CH4</text>
<text x="98.7" y="123.7">50SERVO_PWM TIM2 CH1</text>
<text x="25.4" y="141.5">Brake is LOW -&gt; Brake</text>
<text x="116.2" y="146.6">TIM4 CH2</text>
<text x="116.2" y="144.1">TIM4 CH1</text>
<text x="32.4" y="164.4">EMG is HIGH -&gt; EMG OFF</text>
</g>
<text font-size="1.8" fill="#000084" x="321.4" y="340.5">GND8</text>
<g font-size="1.4" fill="#008484">
<text x="317.2" y="23.2">DIODE</text>
<text x="318.5" y="21.3">D9</text>
<text x="422.6" y="23.2">DIODE</text>
<text x="423.5" y="21.3">D15</text>
<text x="67.1" y="28.2">D7</text>
<text x="65.7" y="30.2">DIODE</text>
<text x="317.2" y="59.4">DIODE</text>
<text x="318.1" y="57.4">D10</text>
<text x="422.6" y="59.4">DIODE</text>
<text x="423.5" y="57.4">D16</text>
<text x="42.8" y="97.7" transform="rotate(-90 42.8 97.7)">DIODE</text>
<text x="44.7" y="96.3" transform="rotate(-90 44.7 96.3)">D1</text>
<text x="318.1" y="100.6">D11</text>
<text x="423.5" y="100.6">D17</text>
<text x="317.2" y="102.6">DIODE</text>
<text x="422.6" y="102.6">DIODE</text>
<text x="536.2" y="105.1">DIODE</text>
<text x="537.2" y="103.2">D21</text>
<text x="318.1" y="136.8">D12</text>
<text x="423.5" y="136.8">D18</text>
<text x="317.2" y="138.8">DIODE</text>
<text x="422.6" y="138.8">DIODE</text>
<text x="534.9" y="153.9">DIODE</text>
<text x="535.9" y="152">D27</text>
<text x="317.2" y="181.9">DIODE</text>
<text x="318.1" y="180">D13</text>
<text x="422.6" y="181.9">DIODE</text>
<text x="423.5" y="180">D19</text>
<text x="317.2" y="218.1">DIODE</text>
<text x="318.1" y="216.2">D14</text>
<text x="422.6" y="218.1">DIODE</text>
<text x="423.5" y="216.2">D20</text>
<text x="122.9" y="250.5">DIODE</text>
<text x="123.8" y="248.6">D28</text>
<text x="386.4" y="272.1">DIODE</text>
<text x="387.7" y="270.2">D8</text>
<text x="528" y="303.9">DIODE</text>
<text x="528.9" y="301.9">D29</text>
</g>
<g font-size="1.4" fill="#840000">
<text x="315.8" y="25.3">2</text>
<text x="322.2" y="25.3">1</text>
<text x="421.3" y="25.3">2</text>
<text x="427.6" y="25.3">1</text>
<text x="64.4" y="32.3">2</text>
<text x="70.7" y="32.3">1</text>
<text x="315.8" y="61.5">2</text>
<text x="322.2" y="61.5">1</text>
<text x="421.3" y="61.5">2</text>
<text x="427.6" y="61.5">1</text>
<text x="39.1" y="92.6" transform="rotate(-90 39.1 92.6)">2</text>
<text x="39.1" y="99" transform="rotate(-90 39.1 99)">1</text>
<text x="315.8" y="104.7">2</text>
<text x="322.2" y="104.7">1</text>
<text x="421.3" y="104.7">2</text>
<text x="427.6" y="104.7">1</text>
<text x="534.9" y="107.2">2</text>
<text x="541.3" y="107.2">1</text>
<text x="315.8" y="140.9">2</text>
<text x="322.2" y="140.9">1</text>
<text x="421.3" y="140.9">2</text>
<text x="427.6" y="140.9">1</text>
<text x="533.7" y="156.1">1</text>
<text x="540" y="156.1">2</text>
<text x="315.8" y="184.1">2</text>
<text x="322.2" y="184.1">1</text>
<text x="421.3" y="184.1">2</text>
<text x="427.6" y="184.1">1</text>
<text x="315.8" y="220.3">2</text>
<text x="322.2" y="220.3">1</text>
<text x="421.3" y="220.3">2</text>
<text x="427.6" y="220.3">1</text>
<text x="121.5" y="252.6">2</text>
<text x="127.9" y="252.6">1</text>
<text x="385.1" y="274.2">2</text>
<text x="391.4" y="274.2">1</text>
<text x="526.7" y="306">2</text>
<text x="533" y="306">1</text>
</g>
</g></defs>
<g fill="none" stroke="#840000" stroke-width=".26">
<path d="M10 10.2h574v400h-574zM12 12.2h570v396h-570zM60 10.2v2M110 10.2v2M160 10.2v2M210 10.2v2M260 10.2v2M290.2 19.9v2.7M310 10.2v2M360 10.2v2M395.6 19.9v2.7M410 10.2v2"/>
<path d="M460 10.2v2M510 10.2v2M536.5 11.8h.8M560 10.2v2M16.1 38.9h2.1v5.1h-2.1zM17.1 37.6v1.3M24.1 37.6v2.8M31.4 38.9h2v5.1h-2zM32.4 32.6h5.1M32.4 35.1h5.1M37.5 30h10.1v10.2h-10.1zM37.5 37.6h-5.1v1.3"/>
<path d="M38.7 21.8h2.8M43.6 21.8h2.8M47.6 32.6h5.1M47.6 35.1h5.1M47.6 37.6h5.1M54 32.6h.5l.4-.6 .4 .2 .2 .4 .4-.6 .4 .2 .2 .4 .4-.6 .5 .2 .1 .4 .4-.6 .5 .2 .1 .4h.6M55.2 35.1v2.8M55.2 39.9v2.8M62.9 32.6h3.8M62.9 33.8v2.8M62.9 38.7v2.7M69.2 32.6h3.8"/>
<path d="M69.2 31.3v2.5M73.7 29.5h3.9v2.3h-3.9l-.7-1.2zM78.7 31.9v1.3h1.3l-1.3 1.3-1.2-1.3h1.2M81.3 31.9h2.5M81.3 37h2.5M86.2 22.5h4l.6 1.2-.6 1.1h-4zM87.9 34.7l-3.2 2M88.9 34.5h2.5M91.1 28.1h2v5.1h-2zM92.1 26.8v1.3M92.1 33.2v1.3M92.7 34.5h5.3"/>
<path d="M95.1 38.4h4l.6 1.1-.6 1.2h-4zM98 32.6v3.8M98.6 32.7h2.5v3.5h-.8M98.6 32.2v1M98.6 34v1M98.6 35.7v1M98.6 36.2h1.7M100.3 26.8v7.7h-1.7M100.3 36.2v3.3M100.3 26.8l-.7 1.3M100.3 26.8l.8 1.3M100.7 34.2h.8l-.4 .6z"/>
<path d="M101.6 34.7l-1 .3M108.6 30l-.8 1.3M108.6 30v2.6M108.6 33.8v2.8M108.6 38.7v2.7M108.6 30l.7 1.3M109.2 32.6h5.1M114.3 30h12.7v8.9h-12.7zM120.6 38.9v6.4h1.3l-1.3 1.2-1.2-1.2h1.2M127 32.6h5.1M132.7 30v2.6M132.7 33.8v2.8"/>
<path d="M132.7 38.7v2.7M132.7 30l-.7 1.3M132.7 30l.8 1.3M290.2 24.7v4h1.3l-1.3 1.3-1.3-1.3h1.3M299.1 31.9h2.5M299.1 37h2.5M301.6 29.4h17.8v20.3h-17.8zM314.3 25.6h3.8M319.4 31.9h2.5M319.4 37h2.5M320.7 24.3v2.5M320.7 25.6h3.8"/>
<path d="M324.5 33.2v2.8M324.5 38v2.8M330.8 39.5h1.3M332.1 38.5h5.1v2.1h-5.1zM337.2 39.5h6.3M338.5 37h5M343.5 31.9h17.8v22.9h-17.8zM361.3 37h5.1M361.3 39.5h5.1M361.3 34.5h5.1M395.6 24.7v4h1.3l-1.3 1.3-1.3-1.3h1.3M404.5 31.9h2.5"/>
<path d="M404.5 37h2.5M407 29.4h17.8v20.3h-17.8zM419.7 25.6h3.8M424.8 31.9h2.6M424.8 37h2.6M426.1 24.3v2.5M426.1 25.6h3.8M429.9 33.2v2.8M429.9 38v2.8M436.2 39.5h1.3M437.5 38.5h5.1v2.1h-5.1zM442.6 39.5h6.3"/>
<path d="M443.9 37h5M448.9 31.9h17.8v22.9h-17.8zM466.7 37h5.1M466.7 39.5h5.1M466.7 34.5h5.1M513.7 25.6h12.7v12.7h-12.7zM17.1 44v2.5h1.3l-1.3 1.3-1.2-1.3h1.2M24.1 42.5v2.8M32.4 44v1.3M62.9 42.7v1.3h1.2l-1.2 1.3-1.3-1.3h1.3M68.6 59.9v5.3M68.6 59.9l-.8 1.2"/>
<path d="M68.6 59.9l.7 1.2M227.3 50.3h3.8M231.1 58.6l7.7 3.8-7.7 3.8zM231.1 46.5l7.7 3.8-7.7 3.8zM240 50.3h2.6M290.2 56v2.8M292.4 43.3h2v5.1h-2zM293.4 42.1v1.2M293.4 48.4v1.3M299.1 49.7v1.3h1.3l-1.3 1.2-1.3-1.2h1.3M299.1 42.1h2.5M299.1 47.2h2.5"/>
<path d="M319.4 42.1h2.5M319.4 47.2h2.5M330.8 44.6h1.3M332.1 43.6h5.1v2h-5.1zM337.2 44.6h6.3M338.5 47.2h5M338.5 49.7h5M343.5 42.1h-5v1.2h1.2l-1.2 1.3-1.3-1.3h1.3M361.3 42.1h5.1M361.3 47.2h5.1M361.3 49.7h5.1M361.3 44.6h5.1"/>
<path d="M361.3 52.2h5.1M368.3 45.9l1-.6-1-.7-1 .7 1 .6v1.3M368.3 47.2h.1M395.6 56v2.8M397.8 43.3h2v5.1h-2zM398.8 42.1v1.2M398.8 48.4v1.3M404.5 49.7v1.3h1.3l-1.3 1.2-1.3-1.2h1.3M404.5 42.1h2.5M404.5 47.2h2.5M424.8 42.1h2.6M424.8 47.2h2.6"/>
<path d="M436.2 44.6h1.3M437.5 43.6h5.1v2h-5.1zM442.6 44.6h6.3M443.9 47.2h5M443.9 49.7h5M448.9 42.1h-5v1.2h1.2l-1.2 1.3-1.3-1.3h1.3M466.7 42.1h5.1M466.7 47.2h5.1M466.7 49.7h5.1M466.7 44.6h5.1M466.7 52.2h5.1M473.7 45.9l1-.6-1-.7-1 .7 1 .6v1.3"/>
<path d="M473.7 47.2h.1M513.7 40.8h12.7v12.7h-12.7zM513.7 56h12.7v12.7h-12.7zM10 60.2h2M27.9 67.5v2.8M27.9 72.3v2.8M28.6 66.2h1.9M32.4 75.1v1.3h1.3l-1.3 1.2-1.3-1.2h1.3M34.3 66.2h1.9M36.8 67.5v2.8M36.8 72.3v2.8M68.6 67.2v2.8"/>
<path d="M77.5 62.4v2.8M77.5 67.2v2.8M78.1 78.3l-.8 1.2M78.1 78.3v5.1M78.1 78.3l.8 1.2M86.4 62.4v2.8M86.4 67.2v2.8M95.2 62.4v2.8M95.2 67.2v2.8M104.1 62.4v2.8M104.1 67.2v2.8M113 67.2v4.1h1.3l-1.3 1.3-1.2-1.3h1.2"/>
<path d="M113 62.4v2.8M227.3 62.4h3.8M227.3 74.5h3.8M231.1 70.7l7.7 3.8-7.7 3.8zM240 62.4h2.6M240 74.5h2.6M290.2 60.9v4h1.3l-1.3 1.3-1.3-1.3h1.3M292.4 79.5h2v5.1h-2zM293.4 78.3v1.2M299.1 68.1h2.5M299.1 73.2h2.5M299.1 78.3h2.5"/>
<path d="M301.6 65.6h17.8v20.3h-17.8zM314.3 61.8h3.8M319.4 68.1h2.5M319.4 73.2h2.5M319.4 78.3h2.5M320.7 60.5v2.5M320.7 61.8h3.8M324.5 69.4v2.8M324.5 74.2v2.8M330.8 75.7h1.3M332.1 79.8h5.1v2h-5.1zM332.1 74.7h5.1v2.1h-5.1z"/>
<path d="M337.2 75.7h6.3M338.5 73.2h5M343.5 68.1h17.8v22.9h-17.8zM343.5 78.3h-5v1.2h1.2l-1.2 1.3-1.3-1.3h1.3M361.3 73.2h5.1M361.3 78.3h5.1M361.3 75.7h5.1M361.3 70.7h5.1M395.6 60.9v4h1.3l-1.3 1.3-1.3-1.3h1.3M397.8 79.5h2v5.1h-2zM398.8 78.3v1.2M404.5 68.1h2.5"/>
<path d="M404.5 73.2h2.5M404.5 78.3h2.5M407 65.6h17.8v20.3h-17.8zM419.7 61.8h3.8M424.8 68.1h2.6M424.8 73.2h2.6M424.8 78.3h2.6M426.1 60.5v2.5M426.1 61.8h3.8M429.9 69.4v2.8M429.9 74.2v2.8M436.2 75.7h1.3"/>
<path d="M437.5 79.8h5.1v2h-5.1zM437.5 74.7h5.1v2.1h-5.1zM442.6 75.7h6.3M443.9 73.2h5M448.9 68.1h17.8v22.9h-17.8zM448.9 78.3h-5v1.2h1.2l-1.2 1.3-1.3-1.3h1.3M466.7 73.2h5.1M466.7 78.3h5.1M466.7 75.7h5.1M466.7 70.7h5.1M521.5 77.3h1M522 76.8v1"/>
<path d="M523.2 75.7v2.8M531.6 77.3h1M532.1 76.8v1M533.4 75.7v2.8M539.1 62.4l-.7 1.3M539.1 62.4v2.5M539.1 62.4l.8 1.3M541.7 62.4v1.3h1.2l-1.2 1.2-1.3-1.2h1.3M542.9 73.2v5.3M542.9 73.2l-.7 1.3M542.9 73.2l.8 1.3M543.6 62.4h3.8"/>
<path d="M543.6 64.9h3.8M547.4 61.1h2.5v5.1h-2.5zM547.4 64.8h1.2v.3h-1.2zM547.4 62.3h1.2v.2h-1.2zM551.8 75.7v2.8M582 60.2h2M17.8 86.5h2.5v15.3h-2.5zM19 97.8h1.3v.3h-1.3zM19 95.3h1.3v.2h-1.3zM19 90.2h1.3v.3h-1.3zM19 87.7h1.3v.2h-1.3zM19 92.8h1.3v.2h-1.3z"/>
<path d="M20.3 90.3h8M20.3 87.8h3.8M20.3 92.9h3.8M20.3 95.4h3.8M20.3 98h3.8M24.8 87.8v1.3h1.2l-1.2 1.2-1.3-1.2h1.3M29.2 89.1a3.2 3.2 0 0 1 5.1 0M35.2 90.3h4.2v3.8M38.1 96.7h2.5M39.4 96.7v3.8M47 98l-.8 1.2M47 98v2.5"/>
<path d="M47 98l.8 1.2M54.2 92.2h2.1v5.1h-2.1zM55.2 91v1.2M55.2 97.3v1.3M61 96.1v2.7M65.4 85.9h2.5M67.9 83.4h30.5v83.8h-30.5zM227.3 98.6h3.8M227.3 86.5h3.8M231.1 94.8l7.7 3.8-7.7 3.8zM231.1 82.7l7.7 3.8-7.7 3.8zM240 86.5h2.6"/>
<path d="M290.2 99.2v2.8M293.4 84.6v1.3M299.1 85.9v1.3h1.3l-1.3 1.2-1.3-1.2h1.3M299.1 83.4h2.5M319.4 83.4h2.5M330.8 80.8h1.3M337.2 80.8h6.3M338.5 83.4h5M338.5 85.9h5M361.3 80.8h5.1M361.3 83.4h5.1M361.3 85.9h5.1"/>
<path d="M361.3 88.4h5.1M368.3 82.1l1-.7-1-.6-1 .6 1 .7v1.3M368.3 83.4h.1M395.6 99.2v2.8M398.8 84.6v1.3M404.5 85.9v1.3h1.3l-1.3 1.2-1.3-1.2h1.3M404.5 83.4h2.5M424.8 83.4h2.6M436.2 80.8h1.3M442.6 80.8h6.3M443.9 83.4h5M443.9 85.9h5"/>
<path d="M466.7 80.8h5.1M466.7 83.4h5.1M466.7 85.9h5.1M466.7 88.4h5.1M473.7 82.1l1-.7-1-.6-1 .6 1 .7v1.3M473.7 83.4h.1M523.2 80.1v3.3M533.4 80.1v3.3M542.9 80.6v2.8M551.8 80.6v4h1.3l-1.3 1.3-1.3-1.3h1.3M10 110.2h2M19 100.4h1.3v.2h-1.3z"/>
<path d="M20.3 100.5h3.8M25.4 112.6h2.5M27.9 111.3h5.1M30.5 109.5v1.8M33 112.6h2.6M61 100.9v4h1.2l-1.2 1.3-1.3-1.3h1.3M65.4 116.4h2.5M65.4 113.8h2.5M227.3 110.7h3.8M231.1 106.8l7.7 3.9-7.7 3.8zM290.2 104.1v4h1.3l-1.3 1.3-1.3-1.3h1.3M299.1 111.3h2.5"/>
<path d="M299.1 116.4h2.5M301.6 108.8h17.8v20.3h-17.8zM314.3 104.9h3.8M319.4 111.3h2.5M319.4 116.4h2.5M320.7 103.7v2.5M320.7 104.9h3.8M324.5 112.6v2.8M324.5 117.4v2.8M330.8 118.9h1.3M332.1 117.9h5.1v2h-5.1zM337.2 118.9h6.3"/>
<path d="M338.5 116.4h5M343.5 111.3h17.8v22.9h-17.8zM361.3 116.4h5.1M361.3 118.9h5.1M361.3 113.8h5.1M395.6 104.1v4h1.3l-1.3 1.3-1.3-1.3h1.3M404.5 111.3h2.5M404.5 116.4h2.5M407 108.8h17.8v20.3h-17.8zM419.7 104.9h3.8M424.8 111.3h2.6M424.8 116.4h2.6"/>
<path d="M426.1 103.7v2.5M426.1 104.9h3.8M429.9 112.6v2.8M429.9 117.4v2.8M436.2 118.9h1.3M437.5 117.9h5.1v2h-5.1zM442.6 118.9h6.3M443.9 116.4h5M448.9 111.3h17.8v22.9h-17.8zM466.7 116.4h5.1M466.7 118.9h5.1M466.7 113.8h5.1"/>
<path d="M527 119.5l.8 1.3M527 119.5v2.6M527 119.5l-.7 1.3M533.4 104.9v2.6h3.8M533.4 104.9l-.8 1.3M533.4 104.9l.8 1.3M539.7 106.2v2.6M539.7 107.5h3.9M543.6 106.2l1-.6-1-.7-1.1 .7 1.1 .6v1.3M543.6 107.5h.1M582 110.2h2M26.7 120.2h2.8"/>
<path d="M31.5 120.2h2.8M35.6 120.2v1.3h1.2l-1.2 1.2-1.3-1.2h1.3M65.4 126.5h2.5M65.4 129.1h2.5M222.9 127.6v4h1.3l-1.3 1.3-1.3-1.3h1.3M222.9 120.2l-.8 1.3M222.9 120.2v5.3M222.9 120.2l.7 1.3M231.1 127.8h10.2v15.2h-10.2zM236.2 120.2l-.7 1.3M236.2 120.2v7.6M236.2 120.2l.8 1.3"/>
<path d="M290.2 135.4v2.8M292.4 122.7h2v5.1h-2zM293.4 121.5v1.2M293.4 127.8v1.3M299.1 129.1v1.2h1.3l-1.3 1.3-1.3-1.3h1.3M299.1 121.5h2.5M299.1 126.5h2.5M319.4 121.5h2.5M319.4 126.5h2.5M320.7 139.9v2.5M330.8 124h1.3M332.1 123h5.1v2h-5.1z"/>
<path d="M337.2 124h6.3M338.5 126.5h5M338.5 129.1h5M343.5 121.5h-5v1.2h1.2l-1.2 1.3-1.3-1.3h1.3M361.3 121.5h5.1M361.3 126.5h5.1M361.3 129.1h5.1M361.3 124h5.1M361.3 131.6h5.1M368.3 125.3l1-.7-1-.6-1 .6 1 .7v1.2M368.3 126.5h.1M395.6 135.4v2.8"/>
<path d="M397.8 122.7h2v5.1h-2zM398.8 121.5v1.2M398.8 127.8v1.3M404.5 129.1v1.2h1.3l-1.3 1.3-1.3-1.3h1.3M404.5 121.5h2.5M404.5 126.5h2.5M424.8 121.5h2.6M424.8 126.5h2.6M426.1 139.9v2.5M436.2 124h1.3M437.5 123h5.1v2h-5.1zM442.6 124h6.3"/>
<path d="M443.9 126.5h5M443.9 129.1h5M448.9 121.5h-5v1.2h1.2l-1.2 1.3-1.3-1.3h1.3M466.7 121.5h5.1M466.7 126.5h5.1M466.7 129.1h5.1M466.7 124h5.1M466.7 131.6h5.1M473.7 125.3l1-.7-1-.6-1 .6 1 .7v1.2M473.7 126.5h.1M527 125.9h5.1M527 128.4h5.1"/>
<path d="M532.1 138h10.2v12.7h-10.2zM532.1 123.4h10.2v7.6h-10.2zM534.7 139.2l3.8 1.3h8.9M542.3 125.9h5.1M542.3 128.4h5.1M65.4 159.6h2.5M236.2 143v6.4h1.3l-1.3 1.3-1.3-1.3h1.3M290.2 140.3v4h1.3l-1.3 1.3-1.3-1.3h1.3M292.4 158.9h2v5.1h-2zM293.4 157.6v1.3M299.1 147.5h2.5M299.1 152.6h2.5"/>
<path d="M299.1 157.6h2.5M301.6 144.9h17.8v20.4h-17.8zM314.3 141.1h3.8M319.4 147.5h2.5M319.4 152.6h2.5M319.4 157.6h2.5M320.7 141.1h3.8M324.5 148.8v2.8M324.5 153.6v2.8M330.8 155.1h1.3M332.1 154.1h5.1v2h-5.1zM332.1 159.2h5.1v2h-5.1z"/>
<path d="M337.2 155.1h6.3M338.5 152.6h5M343.5 147.5h17.8v22.8h-17.8zM343.5 157.6h-5v1.3h1.2l-1.2 1.3-1.3-1.3h1.3M361.3 152.6h5.1M361.3 157.6h5.1M361.3 155.1h5.1M361.3 150h5.1M395.6 140.3v4h1.3l-1.3 1.3-1.3-1.3h1.3M397.8 158.9h2v5.1h-2zM398.8 157.6v1.3M404.5 147.5h2.5"/>
<path d="M404.5 152.6h2.5M404.5 157.6h2.5M407 144.9h17.8v20.4h-17.8zM419.7 141.1h3.8M424.8 147.5h2.6M424.8 152.6h2.6M424.8 157.6h2.6M426.1 141.1h3.8M429.9 148.8v2.8M429.9 153.6v2.8M436.2 155.1h1.3M437.5 154.1h5.1v2h-5.1z"/>
<path d="M437.5 159.2h5.1v2h-5.1zM442.6 155.1h6.3M443.9 152.6h5M448.9 147.5h17.8v22.8h-17.8zM448.9 157.6h-5v1.3h1.2l-1.2 1.3-1.3-1.3h1.3M466.7 152.6h5.1M466.7 157.6h5.1M466.7 155.1h5.1M466.7 150h5.1M508 158.9h2.5M510.5 159.4l4.1 1.8M513.1 158.4v2"/>
<path d="M517.8 154.5h2v5.1h-2zM518.8 153.2v1.3M518.8 159.6v1.2M524.8 159.6v3.8M525.3 159.2v1M525.3 159.7h1.7M525.8 141.8l1-.7-1-.6-1 .6 1 .7v1.2M525.8 143h.1M527 159.7h.8v3.5h-2.5M527 156.4v3.3M527 148.1h8.9M527 140.5h5.1"/>
<path d="M532.1 156.4h3.8M534.7 141.8v1.2h-7.7M535.9 145.6h2.6v3.8h-2.6zM535.9 145.6l2.6 3.8M535.9 155.1v2.5M538.5 148.1h8.9M538.5 156.4h3.8M10 160.2h2M65.4 162.1h2.5M65.4 164.6h2.5M88.3 169.7v1.3h1.2l-1.2 1.3-1.3-1.3h1.3M290.2 178.6v2.8"/>
<path d="M293.4 164v1.3M299.1 165.3v1.2h1.3l-1.3 1.3-1.3-1.3h1.3M299.1 162.7h2.5M319.4 162.7h2.5M330.8 160.2h1.3M337.2 160.2h6.3M338.5 162.7h5M338.5 165.3h5M361.3 160.2h5.1M361.3 162.7h5.1M361.3 165.3h5.1M361.3 167.8h5.1"/>
<path d="M368.3 161.5l1-.7-1-.6-1 .6 1 .7v1.2M368.3 162.7h.1M395.6 178.6v2.8M398.8 164v1.3M404.5 165.3v1.2h1.3l-1.3 1.3-1.3-1.3h1.3M404.5 162.7h2.5M424.8 162.7h2.6M436.2 160.2h1.3M442.6 160.2h6.3M443.9 162.7h5M443.9 165.3h5M466.7 160.2h5.1"/>
<path d="M466.7 162.7h5.1M466.7 165.3h5.1M466.7 167.8h5.1M473.7 161.5l1-.7-1-.6-1 .6 1 .7v1.2M473.7 162.7h.1M510.5 164h-2.5v1.3h1.3l-1.3 1.2-1.3-1.2h1.3M515.6 161.5h2.6M519.4 161.5h5.4M525.3 161.5h1.7v5M525.3 161v1M525.3 162.7v1M527.4 161.2h.8l-.4 .6z"/>
<path d="M528.3 161.7l-1 .3M535.6 167.2h2v5.1h-2zM536.6 172.3v1.2M541.9 164v3.8M541.9 165.9h-5.3v1.3M542.4 165.9h1.8v5.1M542.4 163.6v1M542.4 165.4v1M542.4 167.2v1M542.4 164.1h1.8M544.2 164.1h.8v3.6h-2.6M544.2 160.8v3.3"/>
<path d="M544.4 165.4l1.1 .3M545 165.5l.3 .7h-.7zM553.1 165.9a3.2 3.2 0 0 0 0 5.1M554.4 171.9v5.4h1.2l-1.2 1.3-1.3-1.3h1.3M554.4 160.8v4.2M582 160.2h2M290.2 183.4v4.1h1.3l-1.3 1.3-1.3-1.3h1.3M299.1 195.7h2.5M299.1 190.7h2.5M301.6 188.1h17.8v20.3h-17.8zM314.3 184.3h3.8M319.4 195.7h2.5"/>
<path d="M319.4 190.7h2.5M320.7 184.3h3.8M320.7 183v2.6M324.5 191.9v2.8M324.5 196.8v2.8M330.8 198.3h1.3M332.1 197.3h5.1v2h-5.1zM337.2 198.3h6.3M338.5 195.7h5M343.5 190.7h17.8v22.8h-17.8zM361.3 195.7h5.1M361.3 198.3h5.1"/>
<path d="M361.3 193.2h5.1M395.6 183.4v4.1h1.3l-1.3 1.3-1.3-1.3h1.3M404.5 195.7h2.5M404.5 190.7h2.5M407 188.1h17.8v20.3h-17.8zM419.7 184.3h3.8M424.8 195.7h2.6M424.8 190.7h2.6M426.1 183v2.6M426.1 184.3h3.8M429.9 191.9v2.8M429.9 196.8v2.8"/>
<path d="M436.2 198.3h1.3M437.5 197.3h5.1v2h-5.1zM442.6 198.3h6.3M443.9 195.7h5M448.9 190.7h17.8v22.8h-17.8zM466.7 195.7h5.1M466.7 198.3h5.1M466.7 193.2h5.1M525.1 194.5v2.5h1.3M525.1 194.5l-.7 1.2M525.1 194.5l.8 1.2M526.4 196h5.1v2h-5.1z"/>
<path d="M531.5 197h8.9M535.3 195.7l2.5 1.3-2.5 1.3zM537.8 195.7v2.6M539.9 195.5v-.8h-.8h.8l-1.5 1.6M541.1 195.5v-.8h-.7h.7l-1.5 1.6M10 210.2h2M52.7 202.7h2.5v25.4h-2.5zM54 219.1h1.2v.3h-1.2zM54 216.6h1.2v.2h-1.2zM54 211.5h1.2v.3h-1.2zM54 209h1.2v.2h-1.2zM54 206.4h1.2v.3h-1.2z"/>
<path d="M54 203.9h1.2v.2h-1.2zM54 214h1.2v.3h-1.2zM55.2 206.5h3.9M55.2 209.1h3.9M55.2 211.6h3.9M55.2 214.2h3.9M55.2 204h3.9M55.2 216.7h3.9M55.2 219.2h3.9M68.6 206.5h3.8M68.6 209.1h3.8M68.6 211.6h3.8"/>
<path d="M68.6 214.2h3.8M68.6 201.5v2.5h3.8M68.6 216.7h3.8M68.6 219.2h3.8M68.6 201.5l-.8 1.2M68.6 201.5l.7 1.2M72.4 202.7h5.1v25.4h-5.1zM72.4 219.1h1.3v.3h-1.3zM72.4 216.6h1.3v.2h-1.3zM72.4 211.5h1.3v.3h-1.3zM72.4 209h1.3v.2h-1.3zM72.4 206.4h1.3v.3h-1.3z"/>
<path d="M72.4 203.9h1.3v.2h-1.3zM72.4 214h1.3v.3h-1.3zM76.2 219.1h1.3v.3h-1.3zM76.2 216.6h1.3v.2h-1.3zM76.2 211.5h1.3v.3h-1.3zM76.2 209h1.3v.2h-1.3zM76.2 206.4h1.3v.3h-1.3zM76.2 203.9h1.3v.2h-1.3zM76.2 214h1.3v.3h-1.3zM77.5 206.5h3.8M77.5 209.1h3.8M77.5 211.6h3.8"/>
<path d="M77.5 214.2h3.8M77.5 204h3.8M77.5 216.7h3.8M77.5 219.2h3.8M110.1 207.8h2v5.1h-2zM111.1 201.5l-.7 1.2M111.1 201.5v2.5M111.1 206.5v1.3M111.1 212.9v1.3M111.1 201.5l.8 1.2M116.5 205.3h2v5.1h-2zM117.5 204v1.3"/>
<path d="M117.5 210.4v1.2M117.7 215.4h2.1v5.1h-2.1zM118.7 214.2v1.2M123.2 204v2.5h2.8M123.2 204l-.8 1.3M123.2 204l.8 1.3M124.7 212.9h2v5.1h-2zM125.7 211.6v1.3M125.7 218v1.2M128 206.5h2.8M131.4 206.5v1.3h1.3l-1.3 1.3-1.2-1.3h1.2M132.1 206.5h3.8"/>
<path d="M132.1 209.1h3.8M132.1 211.6h3.8M132.1 214.2h3.8M135.9 205.3h2.5v10.1h-2.5zM135.9 214h1.3v.3h-1.3zM135.9 211.5h1.3v.3h-1.3zM135.9 206.4h1.3v.3h-1.3zM135.9 209h1.3v.2h-1.3zM290.2 219.6v4.1h1.3l-1.3 1.3-1.3-1.3h1.3M290.2 214.8v2.8M292.4 202.1h2v5.1h-2zM293.4 200.8v1.3"/>
<path d="M293.4 207.2v1.2M299.1 208.4v1.3h1.3l-1.3 1.3-1.3-1.3h1.3M299.1 200.8h2.5M299.1 205.9h2.5M319.4 200.8h2.5M319.4 205.9h2.5M320.7 219.2v2.6M330.8 203.4h1.3M332.1 202.4h5.1v2h-5.1zM337.2 203.4h6.3M338.5 205.9h5M338.5 208.4h5"/>
<path d="M343.5 200.8h-5v1.3h1.2l-1.2 1.3-1.3-1.3h1.3M361.3 200.8h5.1M361.3 205.9h5.1M361.3 208.4h5.1M361.3 203.4h5.1M361.3 211h5.1M368.3 204.6l1-.6-1-.6-1 .6 1 .6v1.3M368.3 205.9h.1M395.6 219.6v4.1h1.3l-1.3 1.3-1.3-1.3h1.3M395.6 214.8v2.8M397.8 202.1h2v5.1h-2zM398.8 200.8v1.3"/>
<path d="M398.8 207.2v1.2M404.5 208.4v1.3h1.3l-1.3 1.3-1.3-1.3h1.3M404.5 200.8h2.5M404.5 205.9h2.5M424.8 200.8h2.6M424.8 205.9h2.6M426.1 219.2v2.6M436.2 203.4h1.3M437.5 202.4h5.1v2h-5.1zM442.6 203.4h6.3M443.9 205.9h5M443.9 208.4h5"/>
<path d="M448.9 200.8h-5v1.3h1.2l-1.2 1.3-1.3-1.3h1.3M466.7 200.8h5.1M466.7 205.9h5.1M466.7 208.4h5.1M466.7 203.4h5.1M466.7 211h5.1M473.7 204.6l1-.6-1-.6-1 .6 1 .6v1.3M473.7 205.9h.1M525.1 205.9h1.3M525.1 214.8h1.3M526.4 213.8h5.1v2h-5.1zM526.4 204.9h5.1v2h-5.1z"/>
<path d="M531.5 205.9h8.9M531.5 214.8h8.9M535.3 204.6l2.5 1.3-2.5 1.3zM535.3 213.5l2.5 1.3-2.5 1.3zM537.8 204.6v2.6M537.8 213.5v2.6M539.9 204.4v-.8h-.8h.8l-1.5 1.5M539.9 213.3v-.8h-.8h.8l-1.5 1.5M541.1 204.4v-.8h-.7h.7l-1.5 1.5M541.1 213.3v-.8h-.7h.7l-1.5 1.5M582 210.2h2M54 221.7h1.2v.2h-1.2z"/>
<path d="M54 224.2h1.2v.3h-1.2zM54 226.7h1.2v.3h-1.2zM55.2 226.9h3.9M55.2 221.8h3.9M55.2 224.3h3.9M68.6 226.9h3.8M68.6 221.8h3.8M68.6 224.3h3.8M72.4 221.7h1.3v.2h-1.3zM72.4 224.2h1.3v.3h-1.3zM72.4 226.7h1.3v.3h-1.3zM76.2 221.7h1.3v.2h-1.3z"/>
<path d="M76.2 224.2h1.3v.3h-1.3zM76.2 226.7h1.3v.3h-1.3zM77.5 226.9h3.8v1.2h1.2l-1.2 1.3-1.3-1.3h1.3M77.5 221.8h3.8M77.5 224.3h3.8M117.7 224.3h2.1v5.1h-2.1zM118.7 229.4v2.5h1.3l-1.3 1.3-1.2-1.3h1.2M118.7 220.5v1.3M118.7 223.1v1.2M124.7 221.8h2v5.1h-2zM125.7 226.9v2.5h1.3l-1.3 1.3-1.2-1.3h1.2M125.7 220.5v1.3"/>
<path d="M292.4 238.3h2v5.1h-2zM293.4 237v1.3M299.1 226.9h2.5M299.1 231.9h2.5M299.1 237h2.5M301.6 224.3h17.8v20.3h-17.8zM314.3 220.5h3.8M319.4 226.9h2.5M319.4 231.9h2.5M319.4 237h2.5M320.7 220.5h3.8M324.5 228.1v2.8"/>
<path d="M324.5 233v2.8M330.8 234.5h1.3M330.8 239.6h1.3M332.1 233.5h5.1v2h-5.1zM332.1 238.5h5.1v2.1h-5.1zM337.2 234.5h6.3M337.2 239.6h6.3M338.5 231.9h5M343.5 226.9h17.8v22.8h-17.8zM343.5 237h-5v1.3h1.2l-1.2 1.3-1.3-1.3h1.3M361.3 231.9h5.1M361.3 237h5.1"/>
<path d="M361.3 234.5h5.1M361.3 239.6h5.1M361.3 229.4h5.1M397.8 238.3h2v5.1h-2zM398.8 237v1.3M404.5 226.9h2.5M404.5 231.9h2.5M404.5 237h2.5M407 224.3h17.8v20.3h-17.8zM419.7 220.5h3.8M424.8 226.9h2.6M424.8 231.9h2.6"/>
<path d="M424.8 237h2.6M426.1 220.5h3.8M429.9 228.1v2.8M429.9 233v2.8M436.2 234.5h1.3M436.2 239.6h1.3M437.5 233.5h5.1v2h-5.1zM437.5 238.5h5.1v2.1h-5.1zM442.6 234.5h6.3M442.6 239.6h6.3M443.9 231.9h5M448.9 226.9h17.8v22.8h-17.8z"/>
<path d="M448.9 237h-5v1.3h1.2l-1.2 1.3-1.3-1.3h1.3M466.7 231.9h5.1M466.7 237h5.1M466.7 234.5h5.1M466.7 239.6h5.1M466.7 229.4h5.1M525.1 221.1l-.7 1.3M525.1 221.1v2.6h1.3M525.1 230v2.6h1.3M525.1 221.1l.8 1.3M525.1 230l-.7 1.3M525.1 230l.8 1.3"/>
<path d="M526.4 222.7h5.1v2h-5.1zM526.4 231.6h5.1v2h-5.1zM531.5 232.6h8.9v1.2h1.3l-1.3 1.3-1.3-1.3h1.3M531.5 223.7h8.9M535.3 222.4l2.5 1.3-2.5 1.3zM535.3 231.3l2.5 1.3-2.5 1.2zM537.8 222.4v2.6M537.8 231.3v2.5M539.9 222.2v-.8h-.8h.8l-1.5 1.5M539.9 231.1v-.8h-.8h.8l-1.5 1.5M541.1 222.2v-.8h-.7h.7l-1.5 1.5M541.1 231.1v-.8h-.7h.7l-1.5 1.5"/>
<path d="M49.5 254.8v2.5M49.5 254.8l-.7 1.3M49.5 254.8l.8 1.3M63.5 257.3h2.8M63.5 259.9h2.8M68.3 257.3h7.9M68.3 259.9h7.9M71.1 254.8h5.1M76.2 252.3h12.7v25.4h-12.7zM117.5 259.5h5.1v2h-5.1zM120 252.9h3.8M126.4 252.9h3.8"/>
<path d="M126.4 251.6v2.6M130.8 250.4l-.8 1.2M130.8 250.4v2.5M130.8 250.4l.8 1.2M131.4 252.9h2.6M134 251.6h3.5v5.1h-3.5zM134 255.4h-2.6v2.6l-1.9 1.9M137.5 251.6l2.6-2.5v10.1l-2.6-2.5M293.4 243.4v1.2M299.1 244.6v1.3h1.3l-1.3 1.3-1.3-1.3h1.3M299.1 242.1h2.5M319.4 242.1h2.5"/>
<path d="M338.5 242.1h5M338.5 244.6h5M361.3 242.1h5.1M361.3 244.6h5.1M361.3 247.2h5.1M368.3 240.8l1-.6-1-.6-1 .6 1 .6v1.3M368.3 242.1h.1M398.8 243.4v1.2M404.5 244.6v1.3h1.3l-1.3 1.3-1.3-1.3h1.3M404.5 242.1h2.5M424.8 242.1h2.6M443.9 242.1h5"/>
<path d="M443.9 244.6h5M466.7 242.1h5.1M466.7 244.6h5.1M466.7 247.2h5.1M473.7 240.8l1-.6-1-.6-1 .6 1 .6v1.3M473.7 242.1h.1M513.1 250.4h2.5v5h-2.5zM514.3 254h1.3v.3h-1.3zM514.3 251.5h1.3v.3h-1.3zM515.6 251.6h3.8M515.6 254.2h3.8M522 249.1v2.8"/>
<path d="M522 253.9v2.8M541 250.4h2.6v5h-2.6zM542.3 254h1.3v.3h-1.3zM542.3 251.5h1.3v.3h-1.3zM543.6 251.6h3.8M543.6 254.2h3.8M549.9 249.1v2.8M549.9 253.9v2.8M10 260.2h2M48.5 266.2h2v5.1h-2zM49.5 265v1.2M49.5 271.3v1.3"/>
<path d="M55.5 263.7h2v5.1h-2zM56.5 262.4v1.3M56.5 268.8v1.2M62.2 267.5h2.8M67.1 267.5h2.7M70.5 267.5v1.3h1.3l-1.3 1.2-1.3-1.2h1.3M71.1 262.4h5.1M71.1 265h5.1M71.1 267.5h5.1M71.1 270h5.1M71.1 272.6h5.1M71.1 275.1h5.1"/>
<path d="M116.2 260.5h1.3M122.6 260.5h6.9M129.5 261.2l1.9 1.9v2.5h1.3M132.7 264.6h5.1v2h-5.1zM137.8 265.6h1.3v1.3h1.2l-1.2 1.2-1.3-1.2h1.3M311.8 276.1v4.1h1.3l-1.3 1.3-1.3-1.3h1.3M311.8 268.8v5.3M311.8 268.8l-.8 1.2M311.8 268.8l.7 1.2M320.7 273.9v2.5M320.7 278.3h1.2M320.7 273.9l-.8 1.2"/>
<path d="M320.7 273.9l.7 1.2M321.9 277.3h5.1v2h-5.1zM321.9 279.2h5.1v2h-5.1zM327 278.3h3.8M330.8 278.9l2.6 1.3-2.6 1.3zM330.8 277l2.6 1.3-2.6 1.3zM333.4 278.3h7.6M333.4 277v4.5M335.4 278.7v-.8h-.8h.8l-1.5 1.5M335.4 276.8v-.8h-.8h.8l-1.5 1.5M335.9 276.4h5.1M336.7 278.7v-.8h-.8h.8l-1.5 1.5"/>
<path d="M336.7 276.8v-.8h-.8h.8l-1.5 1.5M341 275.1h12.7v14h-12.7zM353.7 278.3h5.1M353.7 276.4h5.1M363.9 279.6l-.8 1.2M363.9 279.6v2.5M363.9 279.6l.7 1.2M368.3 276.4v1.3h1.3l-1.3 1.2-1.3-1.2h1.3M370.8 271.9h10.2v15.3h-10.2zM371.2 273.7h3.3v.3l-.2 1h-2.8zM373.4 277.4h.6l.6 1.3h1.3M374 277.4h2.6"/>
<path d="M375.3 276.1h-.7l-1.2 1.3h-.7M380.2 279.4h.8v.3h-.8zM380.2 274.4h.8v.2h-.8zM381 279.6h2.5M381 274.5h6.3M389.9 273.2v2.6M393.7 271.9v2.6h-3.8M393.7 271.9l-.8 1.3M393.7 271.9l.8 1.3M407 273.2v2.6h2.8M407 273.2l-.7 1.3M407 273.2l.8 1.3"/>
<path d="M411.9 275.8h2.8M415.3 275.8v1.2h1.3l-1.3 1.3-1.3-1.3h1.3M415.9 278.3h3.8M415.9 275.8h3.8M419.7 274.5h2.6v10.1h-2.6zM419.7 275.6h1.3v.3h-1.3zM419.7 278.2h1.3v.2h-1.3zM462.3 272.6h2.8M467.1 272.6h6.6M469.9 272.6v1.3h1.3l-1.3 1.2-1.3-1.2h1.3M469.9 275.1h3.8M469.9 277.7h3.8"/>
<path d="M473.7 271.3h2.5v7.6h-2.5zM473.7 277.5h1.3v.3h-1.3zM473.7 272.5h1.3v.2h-1.3zM473.7 275h1.3v.3h-1.3zM513.1 263.1h2.5v5h-2.5zM513.1 275.8h2.5v5h-2.5zM514.3 266.7h1.3v.3h-1.3zM514.3 264.2h1.3v.3h-1.3zM514.3 279.4h1.3v.3h-1.3zM514.3 276.9h1.3v.3h-1.3zM515.6 264.3h3.8M515.6 266.9h3.8"/>
<path d="M515.6 277h3.8M515.6 279.6h3.8M522 261.8v2.8M522 266.6v2.8M522 274.5v2.8M522 279.3v2.8M541 263.1h2.6v5h-2.6zM541 275.8h2.6v5h-2.6zM542.3 266.7h1.3v.3h-1.3zM542.3 264.2h1.3v.3h-1.3zM542.3 279.4h1.3v.3h-1.3zM542.3 276.9h1.3v.3h-1.3z"/>
<path d="M543.6 264.3h3.8M543.6 266.9h3.8M543.6 277h3.8M543.6 279.6h3.8M549.9 261.8v2.8M549.9 266.6v2.8M549.9 274.5v2.8M549.9 279.3v2.8M582 260.2h2M119.4 289.7h5.1M119.4 297.3h5.1M124.5 287.2h12.7v12.7h-12.7z"/>
<path d="M124.5 293.5h-5.1v1.3h1.2l-1.2 1.3-1.3-1.3h1.3M133.3 289.7l-2.5 3.8M137.2 293.5h5v1.3h1.3l-1.3 1.3-1.2-1.3h1.2M137.2 289.7h5M137.2 297.3h5M320.7 280.2h1.2M320.7 287.8h1.2M321.9 286.8h5.1v2h-5.1zM327 280.2h3.8M327 287.8h14M329.6 281.1h5v2h-5zM330.8 286.6l2.6 1.2-2.6 1.3z"/>
<path d="M333.4 280.2h7.6M333.4 286.6v2.5M335.4 286.3v-.8h-.8h.8l-1.5 1.6M335.9 282.1h5.1M335.9 284h5.1M335.9 285.9h5.1M336.7 286.3v-.8h-.8h.8l-1.5 1.6M353.7 280.2h5.1M353.7 287.8h5.1M353.7 282.1h5.1M353.7 284h5.1M353.7 285.9h5.1"/>
<path d="M373.4 287.2v2.5M375.8 286.4h.2v.8h-.2zM375.9 287.2v3.8h1.3l-1.3 1.3-1.3-1.3h1.3M380.2 284.5h.8v.3h-.8zM380.2 282h.8v.2h-.8zM381 282.1h2.5M381 284.6h2.5M415.9 280.8h3.8M415.9 283.4h3.8M419.7 283.3h1.3v.2h-1.3zM419.7 280.7h1.3v.3h-1.3zM535.3 293.5h3.8"/>
<path d="M535.3 296.1h3.8M539.1 292.3h2.6v5h-2.6zM539.1 296h1.3v.2h-1.3zM539.1 293.4h1.3v.3h-1.3zM10 310.2h2M189.2 318.9l-.7 1.3M189.2 318.9v3.8M189.2 318.9l.8 1.3M198.1 318.9l-.7 1.3M198.1 318.9v3.8M198.1 318.9l.8 1.3M362.6 317.7v-1.3h-35.6v33h35.6v-7.6"/>
<path d="M522 303.7v1.3h1.2l-1.2 1.2-1.3-1.2h1.3M525.1 303.7v2.5h3.9M525.1 303.7l.8 1.3M525.1 303.7l-.7 1.3M531.5 305v2.5M531.5 306.2h7.6M535.3 303.7h3.8M539.1 302.4h2.6v5.1h-2.6zM539.1 306.1h1.3v.3h-1.3zM539.1 303.6h1.3v.2h-1.3zM582 310.2h2M186.2 335.4h1.8"/>
<path d="M188 332.9v5.1M188.2 322.7h2v5.1h-2zM189.2 338v3.8h1.3l-1.3 1.3-1.2-1.3h1.2M189.2 327.8v1.3M189.2 330.4v2.5M195.1 335.4h1.7M196.8 332.9v5.1M197.1 322.7h2v5.1h-2zM198.1 338v3.8h1.3l-1.3 1.3-1.3-1.3h1.3M198.1 327.8v1.3M198.1 330.4v2.5M217.2 335.4h2.5l-1.3 2.6z"/>
<path d="M217.2 338h2.5M217.4 326.6h2.1v5h-2.1zM218.4 331.6v10.2h1.3l-1.3 1.3-1.2-1.3h1.2M218.4 325.3v1.3M219.2 339.8l1.5 1.5v-.8v.8h-.7M219.2 338.5l1.5 1.5v-.7v.7h-.7M226.7 335.4h2.5l-1.2 2.6zM226.7 338h2.5M226.9 326.6h2.1v5h-2.1zM228 331.6v10.2h1.2l-1.2 1.3-1.3-1.3h1.3M228 325.3v1.3M228.7 339.8l1.6 1.5v-.8v.8h-.8"/>
<path d="M228.7 338.5l1.6 1.5v-.7v.7h-.8M315.6 325.3h1.3M315.6 327.8h1.3M315.6 332.9h1.3M315.6 338h1.3M316.9 324.3h5v2h-5zM316.9 326.8h5v2h-5zM316.9 331.9h5v2h-5zM316.9 337h5v2h-5zM321.9 327.8h5.1M321.9 332.9h5.1M321.9 338h5.1"/>
<path d="M323.2 322.7h3.8M323.2 325.3h3.8M323.2 327.8v2.6h3.8M323.2 327.8l-.7 1.3M323.2 327.8l.8 1.3M327 335.4h-3.8v1.3h1.3l-1.3 1.3-1.3-1.3h1.3M337.2 321.5h7.6l3.8-3.8h1.3v1.2h2.5l1.3-1.2h12.7v24.1h-29.2zM323.2 343.1h3.8M323.2 345.6h3.8M323.2 340.5h3.8M362.6 345.6h3.8M10 360.2h2"/>
<path d="M474 376.2h108v32h-108zM582 360.2h2M474 397.7h108M474 391.7h108M484.6 392.2l-1.3 2M498.3 395.6l-.4-.1-.2 .2 .1 .3 .5 .1v.3h-.6M499.6 395.6l-.4-.1-.3 .3 .1 .6h.6M500.3 395.6h.5l.1 .9M500.3 395v1.5M60 408.2v2M110 408.2v2M160 408.2v2"/>
<path d="M210 408.2v2M260 408.2v2M310 408.2v2M360 408.2v2M410 408.2v2M460 408.2v2M474 404.7h108M474 401.7h108M483.1 402.6l.6-.2 .3 .5-.9 1h.9M494 401.7v3M501.7 406.7h.8M503.2 406.6v.1"/>
<path d="M504.2 405.1l-.4 1.1h.9M504.5 405.7v1M505.2 405a1.71 1.71 0 0 1 0 2.3M506.3 406.2h1.2M508.1 405.7l.4-.5v1.5M508.1 406.7h.9M510 408.2v2M536.5 409.7h.8M558 401.7v6.5M560 408.2v2M566.8 405.1l-1.2 2M567.3 405.7l.4-.5v1.5"/>
<path d="M567.3 406.7h.8"/>
<circle cx="84.3" cy="37" r=".51"/>
<circle cx="84.3" cy="31.9" r=".51"/>
<circle cx="88.4" cy="34.5" r=".51"/>
<circle cx="99.4" cy="34.5" r="2.82"/>
<circle cx="239.4" cy="50.3" r=".63"/>
<circle cx="239.4" cy="62.4" r=".63"/>
<circle cx="239.4" cy="74.5" r=".63"/>
<circle cx="29.2" cy="90.3" r=".89"/>
<circle cx="34.3" cy="90.3" r=".89"/>
<circle cx="239.4" cy="86.5" r=".63"/>
<circle cx="239.4" cy="98.6" r=".63"/>
<circle cx="28.4" cy="112.6" r=".51"/>
<circle cx="32.5" cy="112.6" r=".51"/>
<circle cx="239.4" cy="110.7" r=".63"/>
<circle cx="511" cy="158.9" r=".51"/>
<circle cx="511" cy="164" r=".51"/>
<circle cx="515.1" cy="161.5" r=".51"/>
<circle cx="526.2" cy="161.5" r="2.82"/>
<circle cx="543.3" cy="165.9" r="2.82"/>
<circle cx="554.4" cy="165.9" r=".89"/>
<circle cx="554.4" cy="171" r=".89"/>
<circle cx="130.2" cy="260.5" r="2.82"/>
<circle cx="130.8" cy="293.5" r="2.84"/>
<circle cx="189.2" cy="333.4" r=".51"/>
<circle cx="189.2" cy="337.5" r=".51"/>
<circle cx="198.1" cy="333.4" r=".51"/>
<circle cx="198.1" cy="337.5" r=".51"/>
</g>
<g fill="#ffffc2" stroke="#ffffc2" stroke-width=".26">
<path d="M407 224.3h17.8v20.3h-17.8z"/>
<path d="M407 144.9h17.8v20.4h-17.8z"/>
<path d="M407 188.1h17.8v20.3h-17.8z"/>
<path d="M513.1 250.4h2.5v5h-2.5z"/>
<path d="M541 250.4h2.6v5h-2.6z"/>
<path d="M513.1 263.1h2.5v5h-2.5z"/>
<path d="M541 263.1h2.6v5h-2.6z"/>
<path d="M513.1 275.8h2.5v5h-2.5z"/>
<path d="M301.6 224.3h17.8v20.3h-17.8z"/>
<path d="M407 29.4h17.8v20.3h-17.8z"/>
<path d="M301.6 188.1h17.8v20.3h-17.8z"/>
<path d="M407 108.8h17.8v20.3h-17.8z"/>
<path d="M407 65.6h17.8v20.3h-17.8z"/>
<path d="M370.8 271.9h10.2v15.3h-10.2z"/>
<path d="M337.2 321.5h7.6l3.8-3.8h1.3v1.2h2.5l1.3-1.2h12.7v24.1h-29.2z"/>
<path d="M341 275.1h12.7v14h-12.7z"/>
<path d="M419.7 274.5h2.6v10.1h-2.6z"/>
<path d="M231.1 58.6l7.7 3.8-7.7 3.8z"/>
<path d="M231.1 127.8h10.2v15.2h-10.2z"/>
<path d="M231.1 106.8l7.7 3.9-7.7 3.8z"/>
<path d="M231.1 94.8l7.7 3.8-7.7 3.8z"/>
<path d="M231.1 82.7l7.7 3.8-7.7 3.8z"/>
<path d="M231.1 70.7l7.7 3.8-7.7 3.8z"/>
<path d="M231.1 46.5l7.7 3.8-7.7 3.8z"/>
<path d="M539.1 302.4h2.6v5.1h-2.6z"/>
<path d="M135.9 205.3h2.5v10.1h-2.5z"/>
<path d="M541 275.8h2.6v5h-2.6z"/>
<path d="M17.8 86.5h2.5v15.3h-2.5z"/>
<path d="M52.7 202.7h2.5v25.4h-2.5z"/>
<path d="M72.4 202.7h5.1v25.4h-5.1z"/>
<path d="M473.7 271.3h2.5v7.6h-2.5z"/>
<path d="M539.1 292.3h2.6v5h-2.6z"/>
<path d="M547.4 61.1h2.5v5.1h-2.5z"/>
<path d="M301.6 29.4h17.8v20.3h-17.8z"/>
<path d="M301.6 108.8h17.8v20.3h-17.8z"/>
<path d="M114.3 30h12.7v8.9h-12.7z"/>
<path d="M301.6 65.6h17.8v20.3h-17.8z"/>
<path d="M301.6 144.9h17.8v20.4h-17.8z"/>
<path d="M67.9 83.4h30.5v83.8h-30.5z"/>
</g>
<g fill="none" stroke="#840000" stroke-width=".51">
<path d="M41.8 19.7v4.1M43.3 19.7v4.1M53.2 39.7h4.1M53.2 38.1h4.1M60.8 38.4h4.1M60.8 36.9h4.1M106.6 38.4h4M106.6 36.9h4M130.7 38.4h4M130.7 36.9h4M288.2 24.4h4M288.2 22.9h4"/>
<path d="M322.5 37.8h4M322.5 36.2h4M393.6 24.4h4M393.6 22.9h4M427.9 37.8h4M427.9 36.2h4M22.1 42.2h4.1M22.1 40.7h4.1M288.2 59.1h4M393.6 59.1h4M25.9 72.1h4.1M25.9 70.5h4.1"/>
<path d="M30.5 64.9v2.6M34.3 64.9v2.6M34.8 72.1h4.1M34.8 70.5h4.1M66.5 67h4.1M66.5 65.4h4.1M75.4 67h4.1M75.4 65.4h4.1M84.3 67h4.1M84.3 65.4h4.1M93.2 67h4.1M93.2 65.4h4.1"/>
<path d="M102.1 67h4.1M102.1 65.4h4.1M111 67h4.1M111 65.4h4.1M288.2 60.6h4M322.5 74h4M322.5 72.4h4M393.6 60.6h4M427.9 74h4M427.9 72.4h4M521.2 78.8h4.1M531.4 78.8h4"/>
<path d="M540.9 78.8h4.1M549.8 78.8h4M58.9 99.1h4.1M521.2 80.8a3.3 3.3 0 0 1 4.1 0M531.4 80.8a3.3 3.3 0 0 1 4 0M540.9 80.3h4.1M549.8 80.3h4M29.7 118.2v4M31.2 118.2v4M58.9 100.6h4.1M288.2 103.8h4M288.2 102.3h4"/>
<path d="M322.5 117.1h4M322.5 115.6h4M393.6 103.8h4M393.6 102.3h4M427.9 117.1h4M427.9 115.6h4M220.9 127.3h4M220.9 125.8h4M288.2 140h4M288.2 138.5h4M393.6 140h4M393.6 138.5h4"/>
<path d="M322.5 153.3h4M322.5 151.8h4M427.9 153.3h4M427.9 151.8h4M288.2 183.2h4M288.2 181.7h4M322.5 196.5h4M322.5 195h4M393.6 183.2h4M393.6 181.7h4M427.9 196.5h4M427.9 195h4"/>
<path d="M126.2 204.5v4.1M127.8 204.5v4.1M288.2 219.4h4M288.2 217.8h4M393.6 219.4h4M393.6 217.8h4M322.5 232.7h4M322.5 231.2h4M427.9 232.7h4M427.9 231.2h4M66.5 255.3v6.6M68.1 255.3v6.6"/>
<path d="M129.5 258.6v3.8M519.9 253.7h4.1M519.9 252.1h4.1M547.9 253.7h4M547.9 252.1h4M65.3 265.5v4M66.8 265.5v4M309.8 275.9h4M309.8 274.4h4M410.1 273.7v4.1M411.6 273.7v4.1M465.3 270.6v4"/>
<path d="M466.9 270.6v4M519.9 266.4h4.1M519.9 264.8h4.1M519.9 279.1h4.1M519.9 277.5h4.1M547.9 266.4h4M547.9 264.8h4M547.9 279.1h4M547.9 277.5h4"/>
</g>
<g fill="#840000" stroke="#840000" stroke-width=".26">
<path d="M423.5 219.2l2.6 1.3-2.6 1.3z"/>
<path d="M423.5 139.9l2.6 1.2-2.6 1.3z"/>
<path d="M423.5 183l2.6 1.3-2.6 1.3z"/>
<path d="M554.3 32.7l1.6-.7a1.45 1.45 0 0 0 1.3-.7l.3-.2a.73 .73 0 0 1 1.2-.1 1.67 1.67 0 0 1 1.5 1.4l.2 .7a.73 .73 0 0 1-.1 1.3 5.7 5.7 0 0 0-1.2 4.4 .71 .71 0 0 1 .1 1.1 1.16 1.16 0 0 0 .4 1.7 1.19 1.19 0 0 1-.1 1.6l-.1 .4a2.11 2.11 0 0 0-.1 2.2l-.3 .6v1.1a4.7 4.7 0 0 1-.8 4.2l-.3 1.7-.3-1 .1-1.3a2.97 2.97 0 0 1 .2-2.7 1.94 1.94 0 0 1 .2-1.9l.1-2.2-.2-1.5a2.37 2.37 0 0 1-.1-2.1v-.2a1.96 1.96 0 0 1-.6-2.5v-.2a.49 .49 0 0 1-.4-.5 .49 .49 0 0 1 .4-.5l.2-.1v-1.9a.83 .83 0 0 0-.2-1.3l-.9-.3h-1.1l-.9-.3z"/>
<path d="M539.4 32.3l2.5-.8a4.3 4.3 0 0 0 2.5-.7 2.42 2.42 0 0 0 2 .5 .78 .78 0 0 0 1.2-.1l4.2-1.3 1.3 1a.67 .67 0 0 1 .7 .8l.4 .1-.5 .6a3 3 0 0 0-.8 3.3l.2 1.8 .2 .2-.2 .6a3.6 3.6 0 0 0 .3 3.4 1.25 1.25 0 0 1-.8 1.5l-.7 1.7 .1 2.4-.3 3 .1 1.2 .4 .5a1.45 1.45 0 0 1-.4 1.4l-.1 2-.3 .8-.4 .4-.2-.7 .2-.4a1.44 1.44 0 0 0-.3-1.8l-.3-1.1 .1-3.3-.3-.6 .1-.9-.3-.5a7.4 7.4 0 0 1 .9-4.1l-.1-1.1a6.9 6.9 0 0 1-.2-3.3 1.07 1.07 0 0 1-.3-1.3l-.1-1.5a1.04 1.04 0 0 0-.4-1.4v-.4a1.56 1.56 0 0 0 0-1.5l-.2-.1-.4-.6-1.1-.1a.78 .78 0 0 0-1.1 .4l-.1 1.4-1 .4 .1 2.2a2.1 2.1 0 0 0-.3 2.5l.9 2.5-.3 .8v1.3a1.78 1.78 0 0 1 0 2.3 6.1 6.1 0 0 0-.2 3.5l-.2 2.4 .1 2.2-.5-.8-.5-2.7a3.6 3.6 0 0 1-.5-2.7 1.07 1.07 0 0 1-.1-1.8l.1-.1a3.5 3.5 0 0 0-.2-2.8v-1.7l-.5-1.5a2.21 2.21 0 0 1-.3-2.8l.3-1a2.08 2.08 0 0 0-.9-2v-.5a.73 .73 0 0 0-.7-.9z"/>
<path d="M318.1 219.2l2.6 1.3-2.6 1.3z"/>
<path d="M318.1 183l2.6 1.3-2.6 1.3z"/>
<path d="M423.5 103.7l2.6 1.2-2.6 1.3z"/>
<path d="M423.5 24.3l2.6 1.3-2.6 1.2z"/>
<path d="M423.5 60.5l2.6 1.3-2.6 1.2z"/>
<path d="M375.4 278.3h.8v.8h-.8z"/>
<path d="M376.6 276.8l1.2 .6-1.2 .6z"/>
<path d="M371.6 274h2.5l-.2 .7h-2z"/>
<path d="M387.3 273.2l2.6 1.3-2.6 1.3z"/>
<path d="M338.5 339.9h2.5v1.3h-2.5z"/>
<path d="M338.5 337.4h2.5v1.2h-2.5z"/>
<path d="M338.5 334.8h2.5v1.3h-2.5z"/>
<path d="M338.5 332.3h2.5v1.2h-2.5z"/>
<path d="M338.5 329.7h2.5v1.3h-2.5z"/>
<path d="M338.5 327.2h2.5v1.3h-2.5z"/>
<path d="M338.5 324.7h2.5v1.2h-2.5z"/>
<path d="M338.5 322.1h2.5v1.3h-2.5z"/>
<path d="M542.7 165.9l1-.4v.8z"/>
<path d="M130.2 262.3l.5-.5 .5 1z"/>
<path d="M123.8 251.6l2.6 1.3-2.6 1.3z"/>
<path d="M98.8 34.5l1-.4v.7z"/>
<path d="M529 305l2.5 1.2-2.5 1.3z"/>
<path d="M38.1 94.1h2.5l-1.2 2.6z"/>
<path d="M525.8 161.1l1 .4-1 .3z"/>
<path d="M535.9 156.4l2.6-1.3v2.5z"/>
<path d="M318.1 24.3l2.6 1.3-2.6 1.2z"/>
<path d="M537.2 106.2l2.5 1.3-2.5 1.3z"/>
<path d="M66.7 31.3l2.5 1.3-2.5 1.2z"/>
<path d="M318.1 103.7l2.6 1.2-2.6 1.3z"/>
<path d="M318.1 60.5l2.6 1.3-2.6 1.2z"/>
<path d="M318.1 139.9l2.6 1.2-2.6 1.3z"/>
<circle cx="372.1" cy="277.4" r=".63"/>
<circle cx="375.3" cy="276.1" r=".38"/>
<circle cx="544.2" cy="167.7" r=".28"/>
<circle cx="544.2" cy="164.1" r=".28"/>
<circle cx="100.3" cy="32.7" r=".28"/>
<circle cx="100.3" cy="36.2" r=".28"/>
<circle cx="527.1" cy="163.2" r=".28"/>
<circle cx="527.1" cy="159.7" r=".28"/>
</g>
<g fill="none" stroke="#008484" stroke-width=".26">
<path d="M528.4 135.1l.6 1.6 .5-1.6M533.6 120.8h.8l-.5 .5 .4 .1 .1 .5-.3 .2-.5-.1M540 120.9l.5-.1 .3 .4-.8 .9h.8M544.9 135.6l.5-.5v1.6M544.9 136.7h.9M72.5 155h.7M81.2 274.4h.7M322.8 274.7h.8l-.4 .5 .4 .1v.5h-.8M350.1 279.5a.64 .64 0 0 1 .7 .6 .64 .64 0 0 1-.7 .7zM351.3 280.3h1M372.7 280.5h1.2v.5h-.7v-.5M377.4 281.4a.64 .64 0 0 1 .7 .6 .64 .64 0 0 1-.7 .7z"/>
<path d="M378.6 282.2h1M335.5 324.6a.64 .64 0 0 1 .8 .6 .64 .64 0 0 1-.8 .6z"/>
</g>
<path d="M31.2 63.7h2.3v5h-2.3z" fill="none" stroke="#840000" stroke-width=".3"/>
<path d="M275.6 94.8h210.8M275.6 173.5h210.8M275.6 252.9v-240.7M275.6 252.9h210.8M381 252.9v-240.7M486.4 252.9v-240.7" fill="none" stroke="#0000c2" stroke-width=".26" stroke-dasharray=".4 .4"/>
<g fill="none" stroke="#008400" stroke-width=".26">
<path d="M17.1 37.6h15.3M32.4 35.1h-17.8v10.2h2.5M38.7 21.8h-6.3v10.8M46.4 21.8h6.9v10.8M52.7 32.6h1.3M56.5 35.1h-3.8v2.5M59.1 32.6h3.8v1.2M59.7 31.3v1.3M73 30.6v2M78.7 31.9h2.6M90.8 23.7h1.3v3.1M91.4 34.5h1.3"/>
<path d="M99.7 39.5h.6M109.2 32.6h-.6v1.2M132.1 32.6h.6v1.2M314.3 24.3v1.3M321.9 37h8.9v2.5M321.9 31.9h2.6M324.5 25.6v7.6M366.4 34.5v10.1M419.7 24.3v1.3M427.4 37h8.8v2.5M427.4 31.9h2.5M429.9 25.6v7.6"/>
<path d="M471.8 34.5v10.1M24.1 45.3h9.6M62.9 41.4v1.3h-7.7M108.6 41.4v2.6h24.1v-2.6M242.6 45.9h-15.3v4.4h-1.2M242.6 58h-15.3v4.4h-1.2M292.1 42.1h7M299.1 47.2v2.5h-5.7M324.5 40.8v1.3h-2.6M330.8 44.6v2.6h-8.9M338.5 47.2v2.5M370.2 47.2h-3.8v5"/>
<path d="M397.5 42.1h7M404.5 47.2v2.5h-5.7M429.9 40.8v1.3h-2.5M436.2 44.6v2.6h-8.8M443.9 47.2v2.5M475.6 47.2h-3.8v5M26.7 66.2h1.9M27.9 66.2v1.3M27.9 75.1h8.9M36.2 66.2h1.9M36.8 66.2v1.3M68.6 70h44.4"/>
<path d="M68.6 62.4h44.4M242.6 70h-15.3v4.5h-1.2M292.1 78.3h7M314.3 60.5v1.3M321.9 73.2h8.9v2.5M321.9 68.1h2.6M324.5 61.8v7.6M324.5 77v1.3h-2.6M366.4 70.7v10.1M397.5 78.3h7M419.7 60.5v1.3M427.4 73.2h8.8v2.5"/>
<path d="M427.4 68.1h2.5M429.9 61.8v7.6M429.9 77v1.3h-2.5M471.8 70.7v10.1M523.2 75.7h10.2M539.1 64.9h4.5M541.7 62.4h1.9M542.9 75.7h8.9M24.1 87.8h.7M24.1 98h3.2M24.1 95.4h3.2M24.1 92.9h3.2"/>
<path d="M55.2 98.6v5.1h5.8M55.2 91h10.2M61 96.1h4.4M78.1 80.8h12.7M242.6 82.1h-15.3v4.4h-1.2M242.6 94.1h-15.3v4.5h-1.2M299.1 83.4v2.5h-5.7M330.8 80.8v2.6h-8.9M338.5 83.4v2.5M370.2 83.4h-3.8v5M404.5 83.4v2.5h-5.7M436.2 80.8v2.6h-8.8"/>
<path d="M443.9 83.4v2.5M475.6 83.4h-3.8v5M523.2 83.4h28.6M25.4 112.6v7.6h1.3M35.6 112.6v7.6h-1.3M39.4 100.5h7.6M242.6 106.2h-15.3v4.5h-1.2M314.3 103.7v1.2M321.9 116.4h8.9v2.5M321.9 111.3h2.6M324.5 104.9v7.7M366.4 113.8v10.2"/>
<path d="M419.7 103.7v1.2M427.4 116.4h8.8v2.5M427.4 111.3h2.5M429.9 104.9v7.7M471.8 113.8v10.2M543.6 107.5h1.2M293.4 121.5h5.7M299.1 126.5v2.6h-5.7M314.3 139.9v1.2M324.5 120.2v1.3h-2.6M330.8 124v2.5h-8.9M338.5 126.5v2.6"/>
<path d="M370.2 126.5h-3.8v5.1M397.5 121.5h7M404.5 126.5v2.6h-5.7M419.7 139.9v1.2M429.9 120.2v1.3h-2.5M436.2 124v2.5h-8.8M443.9 126.5v2.6M475.6 126.5h-3.8v5.1M527 125.9v-3.8h20.4v3.8M527 128.4v3.8h20.4M547.4 128.4v12.1M292.1 157.6h7"/>
<path d="M321.9 152.6h8.9v2.5M321.9 147.5h2.6M324.5 141.1v7.7M324.5 156.4v1.2h-2.6M366.4 150v10.2M397.5 157.6h7M427.4 152.6h8.8v2.5M427.4 147.5h2.5M429.9 156.4v1.2h-2.5M429.9 141.1v7.7M471.8 150v10.2M506.7 152.6h12.1v.6"/>
<path d="M524.5 143h2.5M527 148.1v8.3h5.1M542.3 156.4h7M547.4 148.1h1.9v12.7M78.1 169.7h10.2M299.1 162.7v2.6h-5.7M330.8 160.2v2.5h-8.9M338.5 162.7v2.6M370.2 162.7h-3.8v5.1M404.5 162.7v2.6h-5.7M436.2 160.2v2.5h-8.8M443.9 162.7v2.6"/>
<path d="M475.6 162.7h-3.8v5.1M518.2 161.5h1.2M518.8 160.8v.7M525.8 166.5h1.2M535.3 165.9h1.3M536.6 173.5h7.6M544.2 160.8h10.2M544.2 171v5.1h10.2M314.3 183v1.3M321.9 195.7h8.9v2.6M321.9 190.7h2.6M324.5 199.6v1.2h-2.6"/>
<path d="M324.5 184.3v7.6M366.4 193.2v10.2M419.7 183v1.3M427.4 195.7h8.8v2.6M427.4 190.7h2.5M429.9 199.6v1.2h-2.5M429.9 184.3v7.6M471.8 193.2v10.2M540.4 197v35.6M68.6 204v22.9M81.3 204v22.9M111.1 214.2h21"/>
<path d="M117.5 204h-6.4v2.5M117.5 211.6h14.6M123.2 206.5v2.6h8.9M125.7 219.9h1.3M125.7 219.2v1.3M130.8 206.5h1.3M292.1 200.8h7M299.1 205.9v2.5h-5.7M314.3 219.2v1.3M330.8 203.4v2.5h-8.9M338.5 205.9v2.5M370.2 205.9h-3.8v5.1"/>
<path d="M397.5 200.8h7M404.5 205.9v2.5h-5.7M419.7 219.2v1.3M436.2 203.4v2.5h-8.8M443.9 205.9v2.5M475.6 205.9h-3.8v5.1M118.7 222.4h11.5M118.7 221.8v1.3M292.1 237h7M321.9 231.9h8.9v2.6M321.9 226.9h2.6M324.5 220.5v7.6"/>
<path d="M324.5 235.8v1.2h-2.6M330.8 239.6v2.5h-8.9M366.4 229.4v10.2M397.5 237h7M427.4 231.9h8.8v2.6M427.4 226.9h2.5M429.9 235.8v1.2h-2.5M429.9 220.5v7.6M436.2 239.6v2.5h-8.8M471.8 229.4v10.2M56.5 257.3v5.1M62.2 257.3v17.8h8.9"/>
<path d="M63.5 257.3h-14v7.7M63.5 259.9v2.5h7.6M120 252.9v2.5h11.4M130.2 252.9h1.2M299.1 242.1v2.5h-5.7M338.5 242.1v2.5M370.2 242.1h-3.8v5.1M404.5 242.1v2.5h-5.7M443.9 242.1v2.5M475.6 242.1h-3.8v5.1M519.4 254.2v2.5h4.5M523.9 249.1h-4.5v2.5"/>
<path d="M547.4 254.2v2.5h4.4M551.8 249.1h-4.4v2.5M49.5 272.6h21.6M56.5 270h14.6M62.2 265h8.9M69.8 267.5h1.3M320.7 276.4v11.4M358.8 276.4h9.5M407 275.8v2.5h8.9M414.7 275.8h1.2M461 272.6h1.3v2.5h7.6M461 277.7h8.9"/>
<path d="M519.4 279.6v2.5h4.5M519.4 266.9v2.5h4.5M523.9 274.5h-4.5v2.5M523.9 261.8h-4.5v2.5M547.4 266.9v2.5h4.4M547.4 279.6v2.5h4.4M551.8 261.8h-4.4v2.5M551.8 274.5h-4.4v2.5M320.7 282.1h7.6M358.8 282.1h5.1M522 303.7h13.3M189.2 329.1v1.3"/>
<path d="M189.2 329.7h1.9M198.1 329.7h1.9M198.1 329.1v1.3"/>
</g>
<g fill="none" stroke="#000" stroke-width=".26">
<path d="M59.8 33.9h.5M60 33.5v1.1l.3 .2M255.1 45.6v-1.3l.4 .9 .4-.9v1.3M255.1 57.6v-1.2l.4 .9 .4-.9v1.2M255.3 50v-1.3l.5 .9 .4-.9v1.3M279.6 41.7v-1.2l.4 .9 .4-.9v1.2M290.9 40.1h1.1M378 45.6v1.2h.6M385 41.7v-1.2l.4 .9 .4-.9v1.2M396.3 40.1h1.1M483.4 45.6v1.2h.6M255.1 69.7v-1.3l.4 .9 .4-.9v1.3"/>
<path d="M255.3 62.1v-1.3l.5 .9 .4-.9v1.3M255.3 74.1v-1.2l.5 .9 .4-.9v1.2M279.6 77.9v-1.2l.4 .9 .4-.9v1.2M290.9 76.3h1.1M385 77.9v-1.2l.4 .9 .4-.9v1.2M396.3 76.3h1.1M255.1 93.8v-1.3l.4 1 .4-1v1.3M255.1 81.8v-1.3l.4 .9 .4-.9v1.3M255.3 86.2v-1.3l.5 .9 .4-.9v1.3M255.3 98.3v-1.3l.5 .9 .4-.9v1.3M378 82.4h.6l.1-.5-.7-.1v1.2M378.3 82.4l.4 .6"/>
<path d="M483.4 82.4h.6l.1-.5-.7-.1v1.2M483.7 82.4l.4 .6M111.5 105.9v-1.3l.4 .9 .4-.9v1.3M111.5 108.4v-1.2l.4 .9 .4-.9v1.2M111.5 111v-1.3l.4 .9 .4-.9v1.3M111.5 113.5v-1.3l.4 .9 .4-.9v1.3M255.1 105.9v-1.3l.4 .9 .4-.9v1.3M255.3 110.3v-1.2l.5 .9 .4-.9v1.2M396.3 119.5h1.1M548.2 106.3h.4M548.3 105.9v1.1l.3 .2M378 124.9v1.3h.6"/>
<path d="M385 121.1v-1.2l.4 .9 .4-.9v1.2M483.4 124.9v1.3h.6M52.9 141.4v-1.2l.4 .9 .4-.9v1.2M52.9 146.5v-1.2l.4 .9 .4-.9v1.2M52.9 149.1v-1.3l.4 .9 .4-.9v1.3M52.9 144v-1.3l.4 .9 .4-.9v1.3M111.5 144v-1.3l.4 .9 .4-.9v1.3M111.7 150h2.1M113 151.2l.5-.1v-.3h-.4l-.1 .1v.7h.5M113 148.6l.5-.1v-.2l-.4-.1-.1 .2v.6h.5M113.5 146.5v-1.2l.4 .9 .4-.9v1.2M279.6 157.3v-1.3l.4 1 .4-1v1.3"/>
<path d="M290.9 155.7h1.1M385 157.3v-1.3l.4 1 .4-1v1.3M396.3 155.7h1.1M378 161.8l.6-.1 .1-.4-.7-.2v1.3M378.3 161.8l.4 .6M483.4 161.8l.6-.1 .1-.4-.7-.2v1.3M483.7 161.8l.4 .6M290.9 198.9h1.1M396.3 198.9h1.1M279.6 200.5v-1.3l.4 .9 .4-.9v1.3M378 204.3v1.3h.6M385 200.5v-1.3l.4 .9 .4-.9v1.3"/>
<path d="M483.4 204.3v1.3h.6M279.6 236.7v-1.3l.4 .9 .4-.9v1.3M290.9 235.1h1.1M385 236.7v-1.3l.4 .9 .4-.9v1.3M396.3 235.1h1.1M378 241.2l.6-.1 .1-.5-.7-.1v1.3M378.3 241.2l.4 .6M483.4 241.2l.6-.1 .1-.5-.7-.1v1.3M483.7 241.2l.4 .6M531.7 255.8l.6-.1v-.5l-.6-.1v1.3M531.7 247.5v1.3h.6M532 255.8l.4 .6"/>
<path d="M559.6 247.5v1.3h.6M559.6 255.8l.6-.1 .1-.5-.7-.1v1.3M559.9 255.8l.4 .6M359.1 278.6a.64 .64 0 0 1 .8 .6 .64 .64 0 0 1-.8 .7zM360.4 279.4h1M531.7 272.9v1.3h.6M531.7 260.2v1.3h.6M531.7 268.5l.6-.1v-.5l-.6-.1v1.3M532 268.5l.4 .6M559.6 260.2v1.3h.6M559.6 272.9v1.3h.6M559.6 268.5l.6-.1 .1-.5-.7-.1v1.3"/>
<path d="M559.9 268.5l.4 .6M385.2 281.3h1M531.7 281.2l.6-.1v-.5l-.6-.1v1.3M532 281.2l.4 .6M559.6 281.2l.6-.1 .1-.5-.7-.1v1.3M559.9 281.2l.4 .6"/>
</g>
<g fill="none" stroke="#0000c2" stroke-width=".26">
<path d="M119.2 99.9l.4-.4v1.3M122.4 87l.5-.2 .2 .4-.7 .9h.7M119.2 102.2l.5-.1 .3 .3-.8 .9h.8M119.2 100.8h.8M124.3 105l.4-.4v1.3M124.3 105.9h.7M124.6 112.2l-.3 .9h.8M124.9 112.7v.8M121.8 122.7l.3-.3v1.3M121.8 123.7h.7M43.5 140.8l.6-.1v-.4l-.6-.1v1.2h.5l.3-.4-.3-.2M44.8 140.6v.8"/>
<path d="M45.2 140.6l-.4 .2M45.6 140.7h.5l.1 .7M46.2 140.9l-.7 .2 .1 .3h.6M46.8 140.2v1.2M46.9 141l.3 .4M47.2 140.6l-.4 .5M47.7 141l.6-.1v-.2l-.4-.1-.2 .2 .1 .6h.5M124.3 145.4l.5-.1 .2 .3-.7 .9h.7M124.3 143.1l.4-.4v1.3M124.3 144h.7M54.6 163.2l.3-.2 .5 .2v.7l-.2 .4-.6-.2zM56 163.6h.4"/>
<path d="M56.6 163h-.6v1.3M57.1 163.6h.4M57.7 163h-.6v1.3"/>
</g>
<g fill="#008400" stroke="#008400" stroke-width=".26">
<circle cx="462.3" cy="272.6" r=".51"/>
<circle cx="227.3" cy="74.5" r=".51"/>
<circle cx="62.2" cy="265" r=".51"/>
<circle cx="404.5" cy="244.6" r=".51"/>
<circle cx="398.8" cy="121.5" r=".51"/>
<circle cx="527" cy="122.1" r=".51"/>
<circle cx="398.8" cy="42.1" r=".51"/>
<circle cx="293.4" cy="200.8" r=".51"/>
<circle cx="299.1" cy="49.7" r=".51"/>
<circle cx="469.9" cy="272.6" r=".51"/>
<circle cx="293.4" cy="42.1" r=".51"/>
<circle cx="293.4" cy="237" r=".51"/>
<circle cx="227.3" cy="62.4" r=".51"/>
<circle cx="398.8" cy="78.3" r=".51"/>
<circle cx="398.8" cy="237" r=".51"/>
<circle cx="404.5" cy="208.4" r=".51"/>
<circle cx="227.3" cy="110.7" r=".51"/>
<circle cx="299.1" cy="129.1" r=".51"/>
<circle cx="398.8" cy="200.8" r=".51"/>
<circle cx="62.9" cy="42.7" r=".51"/>
<circle cx="70.5" cy="267.5" r=".51"/>
<circle cx="62.9" cy="32.6" r=".51"/>
<circle cx="227.3" cy="98.6" r=".51"/>
<circle cx="404.5" cy="85.9" r=".51"/>
<circle cx="404.5" cy="129.1" r=".51"/>
<circle cx="49.5" cy="257.3" r=".51"/>
<circle cx="293.4" cy="78.3" r=".51"/>
<circle cx="62.2" cy="257.3" r=".51"/>
<circle cx="299.1" cy="165.3" r=".51"/>
<circle cx="404.5" cy="165.3" r=".51"/>
<circle cx="227.3" cy="86.5" r=".51"/>
<circle cx="293.4" cy="157.6" r=".51"/>
<circle cx="404.5" cy="49.7" r=".51"/>
<circle cx="299.1" cy="208.4" r=".51"/>
<circle cx="56.5" cy="257.3" r=".51"/>
<circle cx="398.8" cy="157.6" r=".51"/>
<circle cx="299.1" cy="85.9" r=".51"/>
<circle cx="299.1" cy="244.6" r=".51"/>
<circle cx="547.4" cy="132.2" r=".51"/>
<circle cx="227.3" cy="50.3" r=".51"/>
<circle cx="471.8" cy="37" r=".51"/>
<circle cx="429.9" cy="31.9" r=".51"/>
<circle cx="366.4" cy="244.6" r=".51"/>
<circle cx="366.4" cy="242.1" r=".51"/>
<circle cx="368.3" cy="242.1" r=".51"/>
<circle cx="366.4" cy="234.5" r=".51"/>
<circle cx="366.4" cy="231.9" r=".51"/>
<circle cx="324.5" cy="226.9" r=".51"/>
<circle cx="366.4" cy="208.4" r=".51"/>
<circle cx="366.4" cy="205.9" r=".51"/>
<circle cx="368.3" cy="205.9" r=".51"/>
<circle cx="471.8" cy="39.5" r=".51"/>
<circle cx="366.4" cy="198.3" r=".51"/>
<circle cx="366.4" cy="195.7" r=".51"/>
<circle cx="324.5" cy="190.7" r=".51"/>
<circle cx="366.4" cy="165.3" r=".51"/>
<circle cx="366.4" cy="162.7" r=".51"/>
<circle cx="368.3" cy="162.7" r=".51"/>
<circle cx="366.4" cy="155.1" r=".51"/>
<circle cx="366.4" cy="152.6" r=".51"/>
<circle cx="324.5" cy="147.5" r=".51"/>
<circle cx="366.4" cy="129.1" r=".51"/>
<circle cx="366.4" cy="126.5" r=".51"/>
<circle cx="429.9" cy="111.3" r=".51"/>
<circle cx="471.8" cy="162.7" r=".51"/>
<circle cx="473.7" cy="162.7" r=".51"/>
<circle cx="471.8" cy="155.1" r=".51"/>
<circle cx="471.8" cy="152.6" r=".51"/>
<circle cx="429.9" cy="147.5" r=".51"/>
<circle cx="471.8" cy="129.1" r=".51"/>
<circle cx="471.8" cy="126.5" r=".51"/>
<circle cx="473.7" cy="126.5" r=".51"/>
<circle cx="471.8" cy="118.9" r=".51"/>
<circle cx="471.8" cy="116.4" r=".51"/>
<circle cx="368.3" cy="126.5" r=".51"/>
<circle cx="471.8" cy="85.9" r=".51"/>
<circle cx="471.8" cy="83.4" r=".51"/>
<circle cx="473.7" cy="83.4" r=".51"/>
<circle cx="471.8" cy="75.7" r=".51"/>
<circle cx="471.8" cy="73.2" r=".51"/>
<circle cx="429.9" cy="68.1" r=".51"/>
<circle cx="471.8" cy="49.7" r=".51"/>
<circle cx="471.8" cy="47.2" r=".51"/>
<circle cx="473.7" cy="47.2" r=".51"/>
<circle cx="86.4" cy="70" r=".51"/>
<circle cx="53.3" cy="32.6" r=".51"/>
<circle cx="52.7" cy="35.1" r=".51"/>
<circle cx="55.2" cy="35.1" r=".51"/>
<circle cx="543.6" cy="107.5" r=".51"/>
<circle cx="61" cy="103.7" r=".51"/>
<circle cx="85.7" cy="169.7" r=".51"/>
<circle cx="83.2" cy="169.7" r=".51"/>
<circle cx="80.6" cy="169.7" r=".51"/>
<circle cx="88.3" cy="169.7" r=".51"/>
<circle cx="113" cy="70" r=".51"/>
<circle cx="104.1" cy="70" r=".51"/>
<circle cx="95.2" cy="70" r=".51"/>
<circle cx="32.4" cy="37.6" r=".51"/>
<circle cx="77.5" cy="70" r=".51"/>
<circle cx="104.1" cy="62.4" r=".51"/>
<circle cx="95.2" cy="62.4" r=".51"/>
<circle cx="86.4" cy="62.4" r=".51"/>
<circle cx="77.5" cy="62.4" r=".51"/>
<circle cx="68.6" cy="62.4" r=".51"/>
<circle cx="88.3" cy="80.8" r=".51"/>
<circle cx="85.7" cy="80.8" r=".51"/>
<circle cx="83.2" cy="80.8" r=".51"/>
<circle cx="80.6" cy="80.8" r=".51"/>
<circle cx="78.1" cy="80.8" r=".51"/>
<circle cx="366.4" cy="47.2" r=".51"/>
<circle cx="366.4" cy="118.9" r=".51"/>
<circle cx="366.4" cy="116.4" r=".51"/>
<circle cx="324.5" cy="111.3" r=".51"/>
<circle cx="366.4" cy="85.9" r=".51"/>
<circle cx="366.4" cy="83.4" r=".51"/>
<circle cx="368.3" cy="83.4" r=".51"/>
<circle cx="366.4" cy="75.7" r=".51"/>
<circle cx="366.4" cy="73.2" r=".51"/>
<circle cx="324.5" cy="68.1" r=".51"/>
<circle cx="366.4" cy="49.7" r=".51"/>
<circle cx="471.8" cy="165.3" r=".51"/>
<circle cx="368.3" cy="47.2" r=".51"/>
<circle cx="366.4" cy="39.5" r=".51"/>
<circle cx="366.4" cy="37" r=".51"/>
<circle cx="324.5" cy="31.9" r=".51"/>
<circle cx="132.7" cy="32.6" r=".51"/>
<circle cx="120.6" cy="44" r=".51"/>
<circle cx="17.1" cy="45.3" r=".51"/>
<circle cx="59.7" cy="32.6" r=".51"/>
<circle cx="32.4" cy="45.3" r=".51"/>
<circle cx="24.1" cy="37.6" r=".51"/>
<circle cx="198.1" cy="329.7" r=".51"/>
<circle cx="549.9" cy="261.8" r=".51"/>
<circle cx="549.9" cy="269.4" r=".51"/>
<circle cx="522" cy="261.8" r=".51"/>
<circle cx="522" cy="269.4" r=".51"/>
<circle cx="522" cy="274.5" r=".51"/>
<circle cx="522" cy="282.1" r=".51"/>
<circle cx="549.9" cy="282.1" r=".51"/>
<circle cx="549.9" cy="274.5" r=".51"/>
<circle cx="125.7" cy="211.6" r=".51"/>
<circle cx="118.7" cy="214.2" r=".51"/>
<circle cx="554.4" cy="176.1" r=".51"/>
<circle cx="189.2" cy="329.7" r=".51"/>
<circle cx="131.4" cy="206.5" r=".51"/>
<circle cx="123.2" cy="206.5" r=".51"/>
<circle cx="81.3" cy="224.3" r=".51"/>
<circle cx="81.3" cy="221.8" r=".51"/>
<circle cx="81.3" cy="219.2" r=".51"/>
<circle cx="81.3" cy="216.7" r=".51"/>
<circle cx="81.3" cy="214.2" r=".51"/>
<circle cx="81.3" cy="211.6" r=".51"/>
<circle cx="320.7" cy="280.2" r=".51"/>
<circle cx="130.8" cy="252.9" r=".51"/>
<circle cx="131.4" cy="255.4" r=".51"/>
<circle cx="92.1" cy="34.5" r=".51"/>
<circle cx="108.6" cy="32.6" r=".51"/>
<circle cx="415.3" cy="275.8" r=".51"/>
<circle cx="407" cy="275.8" r=".51"/>
<circle cx="118.7" cy="222.4" r=".51"/>
<circle cx="125.7" cy="219.9" r=".51"/>
<circle cx="111.1" cy="204" r=".51"/>
<circle cx="320.7" cy="282.1" r=".51"/>
<circle cx="429.9" cy="190.7" r=".51"/>
<circle cx="320.7" cy="278.3" r=".51"/>
<circle cx="35.6" cy="120.2" r=".51"/>
<circle cx="525.8" cy="143" r=".51"/>
<circle cx="549.3" cy="156.4" r=".51"/>
<circle cx="527" cy="156.4" r=".51"/>
<circle cx="544.2" cy="173.5" r=".51"/>
<circle cx="536.6" cy="165.9" r=".51"/>
<circle cx="518.8" cy="161.5" r=".51"/>
<circle cx="549.3" cy="160.8" r=".51"/>
<circle cx="540.4" cy="214.8" r=".51"/>
<circle cx="540.4" cy="205.9" r=".51"/>
<circle cx="540.4" cy="232.6" r=".51"/>
<circle cx="542.9" cy="75.7" r=".51"/>
<circle cx="542.9" cy="83.4" r=".51"/>
<circle cx="533.4" cy="83.4" r=".51"/>
<circle cx="551.8" cy="83.4" r=".51"/>
<circle cx="471.8" cy="244.6" r=".51"/>
<circle cx="471.8" cy="242.1" r=".51"/>
<circle cx="473.7" cy="242.1" r=".51"/>
<circle cx="81.3" cy="206.5" r=".51"/>
<circle cx="471.8" cy="234.5" r=".51"/>
<circle cx="471.8" cy="231.9" r=".51"/>
<circle cx="429.9" cy="226.9" r=".51"/>
<circle cx="471.8" cy="208.4" r=".51"/>
<circle cx="471.8" cy="205.9" r=".51"/>
<circle cx="473.7" cy="205.9" r=".51"/>
<circle cx="471.8" cy="198.3" r=".51"/>
<circle cx="471.8" cy="195.7" r=".51"/>
<circle cx="62.2" cy="267.5" r=".51"/>
<circle cx="522" cy="249.1" r=".51"/>
<circle cx="68.6" cy="211.6" r=".51"/>
<circle cx="68.6" cy="214.2" r=".51"/>
<circle cx="68.6" cy="216.7" r=".51"/>
<circle cx="68.6" cy="219.2" r=".51"/>
<circle cx="68.6" cy="221.8" r=".51"/>
<circle cx="68.6" cy="224.3" r=".51"/>
<circle cx="68.6" cy="209.1" r=".51"/>
<circle cx="68.6" cy="206.5" r=".51"/>
<circle cx="81.3" cy="226.9" r=".51"/>
<circle cx="68.6" cy="204" r=".51"/>
<circle cx="81.3" cy="209.1" r=".51"/>
<circle cx="540.4" cy="223.7" r=".51"/>
<circle cx="32.4" cy="75.1" r=".51"/>
<circle cx="36.8" cy="66.2" r=".51"/>
<circle cx="27.9" cy="66.2" r=".51"/>
<circle cx="549.9" cy="256.7" r=".51"/>
<circle cx="549.9" cy="249.1" r=".51"/>
<circle cx="522" cy="256.7" r=".51"/>
</g>
<g fill="none" stroke="#000084" stroke-width=".26">
<path d="M80.7 36.4l1.2 1.2M81.9 36.4l-1.2 1.2M23.5 99.9l1.2 1.2M24.7 99.9l-1.2 1.2M526.4 139.9l1.3 1.2M527.7 139.9l-1.3 1.2M507.4 158.3l1.2 1.2M508.6 158.3l-1.2 1.2M70.5 254.2l1.2 1.2M71.7 254.2l-1.2 1.2M358.2 287.2l1.2 1.2M358.2 285.3l1.2 1.2"/>
<path d="M358.2 283.4l1.2 1.2M359.4 287.2l-1.2 1.2M359.4 285.3l-1.2 1.2M359.4 283.4l-1.2 1.2M372.8 289.1l1.2 1.2M374 289.1l-1.2 1.2M382.9 284l1.2 1.3M384.1 284l-1.2 1.3M534.7 295.5l1.2 1.2M534.7 292.9l1.2 1.2M535.9 295.5l-1.2 1.2M535.9 292.9l-1.2 1.2"/>
<path d="M322.6 322.1l1.2 1.3M323.8 322.1l-1.2 1.3M322.6 345l1.2 1.2M322.6 342.5l1.2 1.2M323.8 345l-1.2 1.2M323.8 342.5l-1.2 1.2M365.8 345l1.2 1.2M367 345l-1.2 1.2"/>
</g>
<use href="#words"/>
</svg>
